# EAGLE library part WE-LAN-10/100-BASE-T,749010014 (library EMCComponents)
LAN-Transformer WE-LAN 10/100 Base T - Compliant with IEEE 802.3 standards - SMD -- Ethernet -- Power over Ethernet -- 1 Gigabit Ethernet -- Compliant with most IC's for ethernet applications like Intel, AMD, Globespan and Realtek -- Hub, Router, Switch

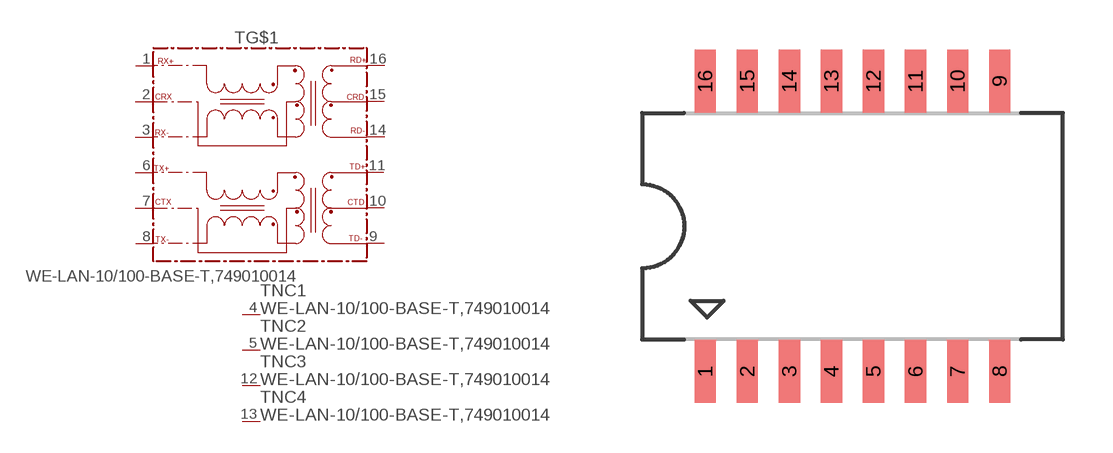
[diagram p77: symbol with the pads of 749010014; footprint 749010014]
Designator prefix T; gates G$1=749010014 NC1=NC NC2=NC NC3=NC NC4=NC

## WE-LAN-10/100-BASE-T,749010014 (COMPANY-URL: http://www.we-online.de; CREATED-BY: Christin Zierenner; CREATED-DATE: June 2012; DATASHEET-URL: http://katalog.we-online.de/kataloge/eisos/media/pdf/749010014.pdf; MANUFACTURER: Würth Elektronik eiSos GmbH)  [749010014]
1  G$1:RX+
2  G$1:CRX
3  G$1:RX-
4  NC1:NC  nc
5  NC2:NC  nc
6  G$1:TX+
7  G$1:CTX
8  G$1:TX-
9  G$1:TD-
10  G$1:CTD
11  G$1:TD+
12  NC3:NC  nc
13  NC4:NC  nc
14  G$1:RD-
15  G$1:CRD
16  G$1:RD+

## Footprint 749010014 (pad centres in mm)
MAX Height =5.08mm
smd 0.64 x 1.91: 1 -4.445,-4.385; 2 -3.175,-4.385; 3 -1.905,-4.385; 4 -0.635,-4.385; 5 0.635,-4.385; 6 1.905,-4.385; 7 3.175,-4.385; 8 4.445,-4.385; 9 4.445,4.385; 10 3.175,4.385; 11 1.905,4.385; 12 0.635,4.385; 13 -0.635,4.385; 14 -1.905,4.385; 15 -3.175,4.385; 16 -4.445,4.385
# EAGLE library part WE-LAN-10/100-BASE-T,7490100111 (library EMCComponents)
LAN-Transformer WE-LAN 10/100 Base T - Compliant with IEEE 802.3 standards - SMD -- Ethernet -- Power over Ethernet -- 1 Gigabit Ethernet -- Compliant with most IC's for ethernet applications like Intel, AMD, Globespan and Realtek -- Hub, Router, Switch

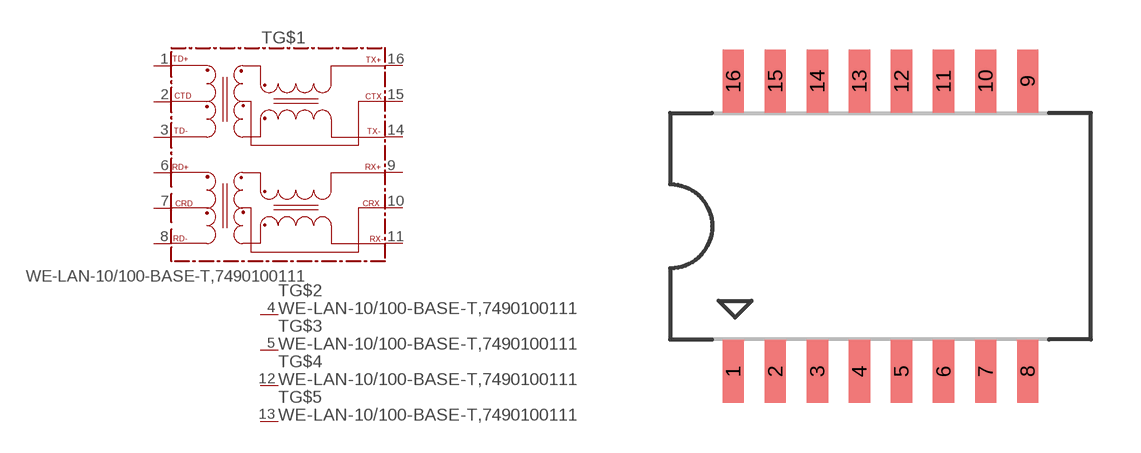
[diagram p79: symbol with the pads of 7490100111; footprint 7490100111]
Designator prefix T; gates G$1=7490100111 G$2=NC G$3=NC G$4=NC G$5=NC

## WE-LAN-10/100-BASE-T,7490100111 (COMPANY-URL: http://www.we-online.de; CREATED-BY: Christin Zierenner; CREATED-DATE: June 2012; DATASHEET-URL: http://katalog.we-online.de/kataloge/eisos/media/pdf/7490100111.pdf; MANUFACTURER: Würth Elektronik eiSos GmbH)  [7490100111]
1  G$1:TD+
2  G$1:CTD
3  G$1:TD-
4  G$2:NC  nc
5  G$3:NC  nc
6  G$1:RD+
7  G$1:CRD
8  G$1:RD-
9  G$1:RX+
10  G$1:CRX
11  G$1:RX-
12  G$4:NC  nc
13  G$5:NC  nc
14  G$1:TX-
15  G$1:CTX
16  G$1:TX+

## Footprint 7490100111 (pad centres in mm)
MAX Height=5.08mm
smd 0.64 x 1.91: 1 -4.445,-4.385; 2 -3.175,-4.385; 3 -1.905,-4.385; 4 -0.635,-4.385; 5 0.635,-4.385; 6 1.905,-4.385; 7 3.175,-4.385; 8 4.445,-4.385; 9 4.445,4.385; 10 3.175,4.385; 11 1.905,4.385; 12 0.635,4.385; 13 -0.635,4.385; 14 -1.905,4.385; 15 -3.175,4.385; 16 -4.445,4.385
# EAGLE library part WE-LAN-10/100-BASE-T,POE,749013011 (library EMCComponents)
LAN-Transformer WE-LAN 10/100 Base Tx - Compliant with IEEE 802.3 standards - SMD -- Ethernet -- Power over Ethernet -- 1 Gigabit Ethernet -- Compliant with most IC's for ethernet applications like Intel, AMD, Globespan and Realtek -- Hub, Router, Switch

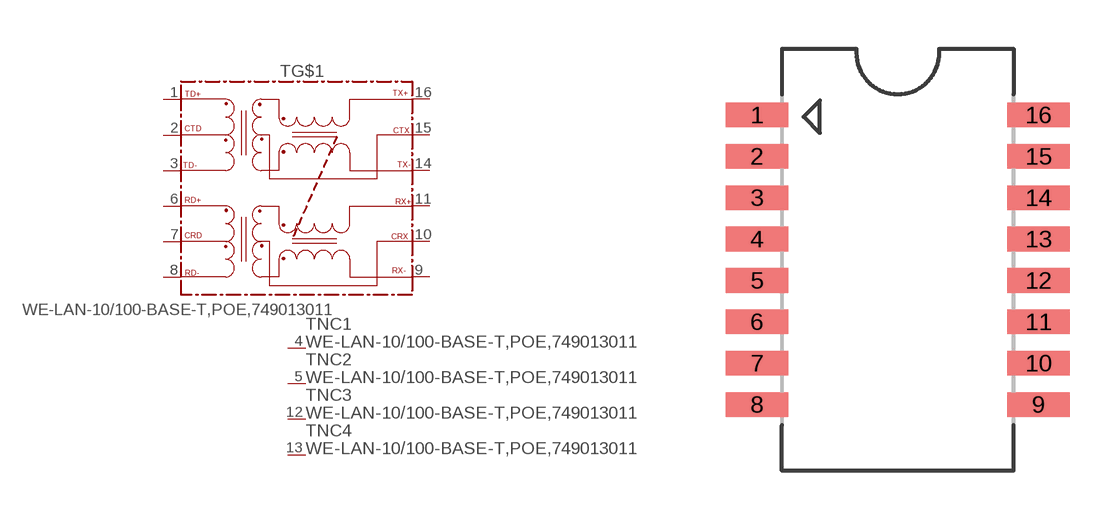
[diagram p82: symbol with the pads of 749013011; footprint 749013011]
Designator prefix T; gates G$1=749013011 NC1=NC NC2=NC NC3=NC NC4=NC

## WE-LAN-10/100-BASE-T,POE,749013011 (COMPANY-URL: http://www.we-online.de; CREATED-BY: Christin Zierenner; CREATED-DATE: June 2012; DATASHEET-URL: http://katalog.we-online.de/kataloge/eisos/media/pdf/749013011.pdf; MANUFACTURER: Würth Elektronik eiSos GmbH)  [749013011]
1  G$1:TD+
2  G$1:CTD
3  G$1:TD-
4  NC1:NC  nc
5  NC2:NC  nc
6  G$1:RD+
7  G$1:CRD
8  G$1:RD-
9  G$1:RX-
10  G$1:CRX
11  G$1:RX+
12  NC3:NC  nc
13  NC4:NC  nc
14  G$1:TX-
15  G$1:CTX
16  G$1:TX+

## Footprint 749013011 (pad centres in mm)
MAX Height = 5.33mm
smd 1.91 x 0.76: 1 -4.317,4.445; 2 -4.317,3.175; 3 -4.317,1.905; 4 -4.317,0.635; 5 -4.317,-0.635; 6 -4.317,-1.905; 7 -4.317,-3.175; 8 -4.317,-4.445; 9 4.317,-4.445; 10 4.317,-3.175; 11 4.317,-1.905; 12 4.317,-0.635; 13 4.317,0.635; 14 4.317,1.905; 15 4.317,3.175; 16 4.317,4.445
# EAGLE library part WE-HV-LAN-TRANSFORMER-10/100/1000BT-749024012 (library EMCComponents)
WE-LAN HV LAN-Transformer Characteristics: •Compliant with IEEE802.3 and 802.3af standards •Operating temperature: 0 °C to +70 °C •SMD •4 kV Hipot test Applications: •Ethernet •Compliant with most IC's for Ethernet applications like Intel, AMD, Conexant, Realtek, etc. •Hub, Router, Switches, medical applications

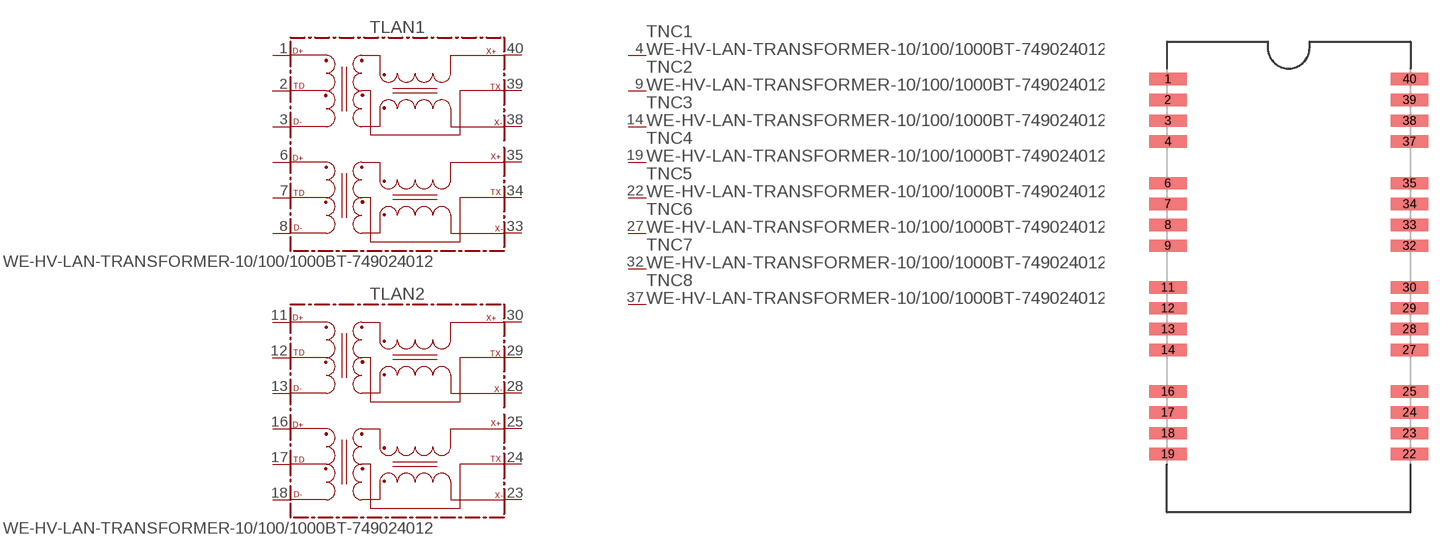
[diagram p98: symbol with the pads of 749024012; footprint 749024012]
Designator prefix T; gates LAN1=749024012 LAN2=749024012 NC1=NC NC2=NC NC3=NC NC4=NC NC5=NC NC6=NC NC7=NC NC8=NC

## WE-HV-LAN-TRANSFORMER-10/100/1000BT-749024012 (COMPANY-URL: http://www.we-online.de; CREATED-BY: Christin Zierenner; CREATED-DATE: July 2012; DATASHEET-URL: http://katalog.we-online.de/kataloge/eisos/media/pdf/749024012.pdf; MANUFACTURER: Würth Elektronik eiSos GmbH)  [749024012]
1  LAN1:D+
2  LAN1:TD
3  LAN1:D-
4  NC1:NC  nc
6  LAN1:D1+
7  LAN1:TD1
8  LAN1:D1-
9  NC2:NC  nc
11  LAN2:D+
12  LAN2:TD
13  LAN2:D-
14  NC3:NC  nc
16  LAN2:D1+
17  LAN2:TD1
18  LAN2:D1-
19  NC4:NC  nc
22  NC5:NC  nc
23  LAN2:X1-
24  LAN2:TX1
25  LAN2:X1+
27  NC6:NC  nc
28  LAN2:X-
29  LAN2:TX
30  LAN2:X+
32  NC7:NC  nc
33  LAN1:X1-
34  LAN1:TX1
35  LAN1:X1+
37  NC8:NC  nc
38  LAN1:X-
39  LAN1:TX
40  LAN1:X+

## Footprint 749024012 (pad centres in mm)
MAX Height=12.70 mm
smd 2.29 x 0.76: 1 -7.365,12.065; 2 -7.365,10.795; 3 -7.365,9.525; 4 -7.365,8.255; 6 -7.365,5.715; 7 -7.365,4.445; 8 -7.365,3.175; 9 -7.365,1.905; 11 -7.365,-0.635; 12 -7.365,-1.905; 13 -7.365,-3.175; 14 -7.365,-4.445; 16 -7.365,-6.985; 17 -7.365,-8.255; 18 -7.365,-9.525; 19 -7.365,-10.795; 22 7.365,-10.795; 23 7.365,-9.525; 24 7.365,-8.255; 25 7.365,-6.985; 27 7.365,-4.445; 28 7.365,-3.175; 29 7.365,-1.905; 30 7.365,-0.635; 32 7.365,1.905; 33 7.365,3.175; 34 7.365,4.445; 35 7.365,5.715; 37 7.365,8.255; 38 7.365,9.525; 39 7.365,10.795; 40 7.365,12.065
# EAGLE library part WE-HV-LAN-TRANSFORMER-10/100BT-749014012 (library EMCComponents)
WE-LAN HV LAN-Transformer Characteristics: •Compliant with IEEE802.3 and 802.3af standards •Operating temperature: 0 °C to +70 °C •SMD •6 kV Hipot test Applications: •Ethernet •Compliant with most IC's for Ethernet applications like Intel, AMD, Conexant, Realtek, etc. •Hub, Router, Switches, medical applications

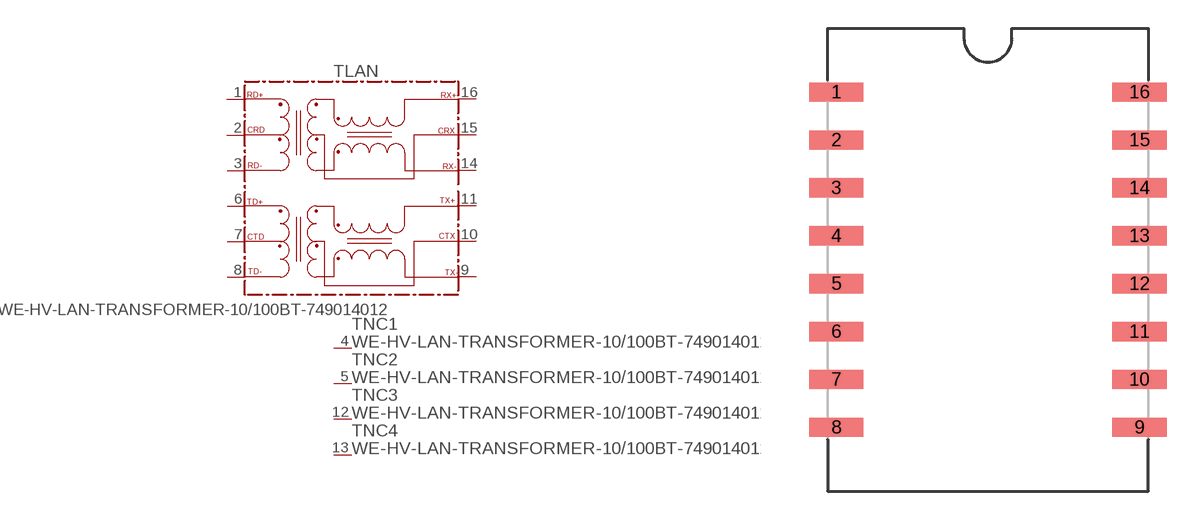
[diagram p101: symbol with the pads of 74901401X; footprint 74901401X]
Designator prefix T; gates LAN=749014012 NC1=NC NC2=NC NC3=NC NC4=NC

## WE-HV-LAN-TRANSFORMER-10/100BT-749014012 (COMPANY-URL: http://www.we-online.de; CREATED-BY: Christin Zierenner; CREATED-DATE: July 2012; DATASHEET-URL: http://katalog.we-online.de/kataloge/eisos/media/pdf/749014012.pdf; MANUFACTURER: Würth Elektronik eiSos GmbH)  [74901401X]
1  LAN:RD+
2  LAN:CRD
3  LAN:RD-
4  NC1:NC  nc
5  NC2:NC  nc
6  LAN:TD+
7  LAN:CTD
8  LAN:TD-
9  LAN:TX-
10  LAN:CTX
11  LAN:TX+
12  NC3:NC  nc
13  NC4:NC  nc
14  LAN:RX-
15  LAN:CRX
16  LAN:RX+

## Footprint 74901401X (pad centres in mm)
MAX Height=10.85 mm
smd 2.87 x 1.02: 1 -8.03,8.89; 2 -8.03,6.35; 3 -8.03,3.81; 4 -8.03,1.27; 5 -8.03,-1.27; 6 -8.03,-3.81; 7 -8.03,-6.35; 8 -8.03,-8.89; 9 8.03,-8.89; 10 8.03,-6.35; 11 8.03,-3.81; 12 8.03,-1.27; 13 8.03,1.27; 14 8.03,3.81; 15 8.03,6.35; 16 8.03,8.89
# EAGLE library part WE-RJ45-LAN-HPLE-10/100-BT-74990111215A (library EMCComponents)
Order Code 74990111215A Design THT xBase-T 10/100 Base-T Ports 1x1 Application Standard HPLE Tab Position Down LED (Left-Right) YELLOW-GREEN EMI Fingers YES

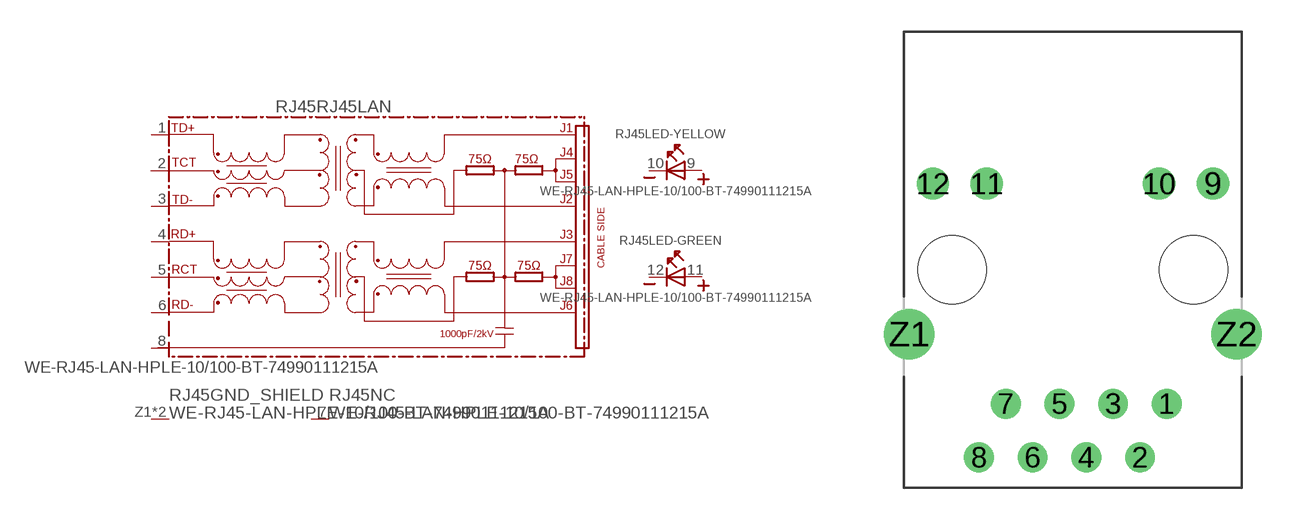
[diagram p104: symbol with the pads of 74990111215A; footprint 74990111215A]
Designator prefix RJ45; gates RJ45LAN=74990111215A LED-YELLOW=LED-2PIN LED-GREEN=LED-2PIN GND_SHIELD=GND_PIN NC=NC

## WE-RJ45-LAN-HPLE-10/100-BT-74990111215A (COMPANY-URL: http://www.we-online.de; CREATED-BY: Christin Zierenner; CREATED-DATE: AUG 2012; DATASHEET-URL: http://katalog.we-online.de/kataloge/eisos/media/pdf/74990111215A.pdf; MANUFACTURER: Würth Elektronik eiSos GmbH)  [74990111215A]
1  RJ45LAN:TD+
2  RJ45LAN:TCT
3  RJ45LAN:TD-
4  RJ45LAN:RD+
5  RJ45LAN:RCT
6  RJ45LAN:RD-
7  NC:NC  nc
8  RJ45LAN:SH  pwr
9  LED-YELLOW:A
10  LED-YELLOW:K
11  LED-GREEN:A
12  LED-GREEN:K
Z1  GND_SHIELD:P$1  pwr
Z2  GND_SHIELD:P$1  pwr

## Footprint 74990111215A (pad centres in mm)
MAX HEIGHT=13.74mm PORTS----1X1 LED --YES
drill 0.9: 1 4.445,-6.35; 2 3.175,-8.89; 3 1.905,-6.35; 4 0.635,-8.89; 5 -0.635,-6.35; 6 -1.905,-8.89; 7 -3.175,-6.35; 8 -4.445,-8.89
drill 1.02: 9 6.625,4.08; 10 4.085,4.08; 11 -4.085,4.08; 12 -6.625,4.08
drill 1.6: Z1 -7.745,-3.05; Z2 7.745,-3.05
hole 3.25 at 5.715,0
hole 3.25 at -5.715,0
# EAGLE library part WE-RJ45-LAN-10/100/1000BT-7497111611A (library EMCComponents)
Order Code 7497111611A Design THT xBase-T 10/100/1000 Base-T Ports 1x1 + 2xUSB Application Standard USB2.0 Tab Position UP LED (Left-Right) GREEN/ORANGE-YELLOW EMI Fingers YES

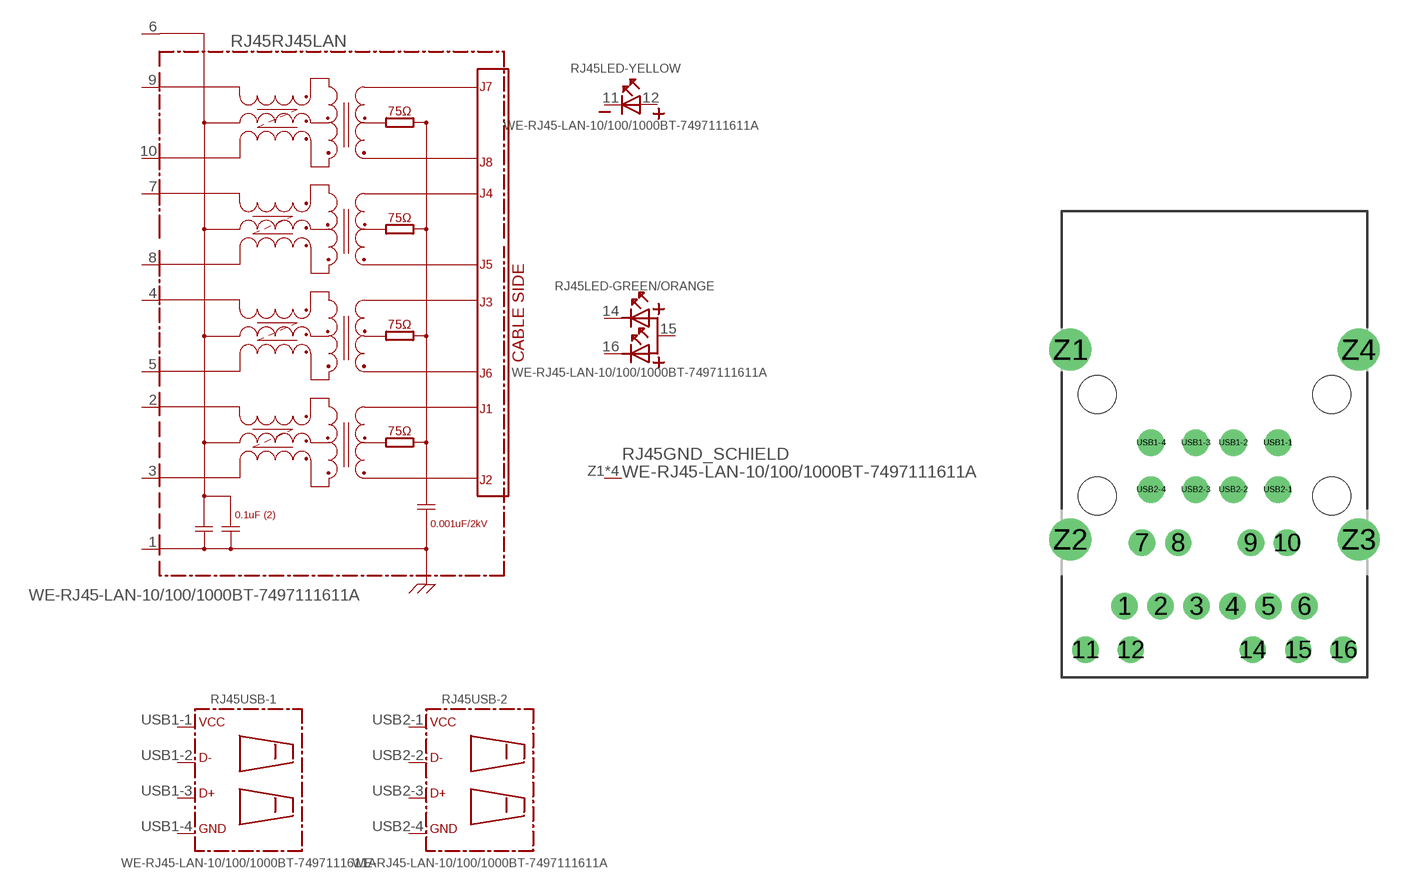
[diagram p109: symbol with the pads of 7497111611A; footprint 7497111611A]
Designator prefix RJ45; gates RJ45LAN=7497111611A LED-YELLOW=LED2PIN LED-GREEN/ORANGE=LED-DUAL1 USB-1=USB2.0 USB-2=USB2.0 GND_SCHIELD=GND_PIN

## WE-RJ45-LAN-10/100/1000BT-7497111611A (COMPANY-URL: http://www.we-online.de; CREATED-BY: Christin Zierenner; CREATED-DATE: AUG 2012; DATASHEET-URL: http://katalog.we-online.de/kataloge/eisos/media/pdf/7497111611A.pdf; MANUFACTURER: Würth Elektronik eiSos GmbH)  [7497111611A]
1  RJ45LAN:1  pwr
2  RJ45LAN:2
3  RJ45LAN:3
4  RJ45LAN:4
5  RJ45LAN:5
6  RJ45LAN:6
7  RJ45LAN:7
8  RJ45LAN:8
9  RJ45LAN:9
10  RJ45LAN:10
11  LED-YELLOW:K
12  LED-YELLOW:A
14  LED-GREEN/ORANGE:K1
15  LED-GREEN/ORANGE:A1
16  LED-GREEN/ORANGE:K2
USB1-1  USB-1:VCC  pwr
USB1-2  USB-1:D-
USB1-3  USB-1:D+
USB1-4  USB-1:GND  pwr
USB2-1  USB-2:VCC  pwr
USB2-2  USB-2:D-
USB2-3  USB-2:D+
USB2-4  USB-2:GND  pwr
Z1  GND_SCHIELD:P$1  pwr
Z2  GND_SCHIELD:P$1  pwr
Z3  GND_SCHIELD:P$1  pwr
Z4  GND_SCHIELD:P$1  pwr

## Footprint 7497111611A (pad centres in mm)
MAX HEIGHT=13.50mm PORTS----1X1 + 2XUSB (USB2.0) LED -YES
drill 0.97: 1 -5.025,-14.35; 2 -3.015,-14.35; 3 -1.005,-14.35; 4 1.005,-14.35; 5 3.015,-14.35; 6 5.025,-14.35; 7 -4.065,-10.8; 8 -2.03,-10.8; 9 2.03,-10.8; 10 4.065,-10.8; 11 -7.225,-16.78; 12 -4.685,-16.78; 14 2.14,-16.78; 15 4.685,-16.78; 16 7.225,-16.78; USB1-1 3.55,-5.21; USB1-2 1.05,-5.21; USB1-3 -1.05,-5.21; USB1-4 -3.55,-5.21; USB2-1 3.55,-7.83; USB2-2 1.05,-7.83; USB2-3 -1.05,-7.83; USB2-4 -3.55,-7.83
drill 1.57: Z1 -8.065,0; Z2 -8.065,-10.62; Z3 8.065,-10.62; Z4 8.065,0
hole 2.13 at 6.565,-2.51
hole 2.13 at -6.565,-2.51
hole 2.13 at -6.565,-8.2
hole 2.13 at 6.565,-8.2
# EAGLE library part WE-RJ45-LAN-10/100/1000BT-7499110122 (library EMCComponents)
Order Code 7499110122 Design THT xBase-T 10/100/1000 Base-T Ports 1x1 Application Standard Tab Position Down LED (Left-Right) YELLOW-GREEN EMI Fingers No

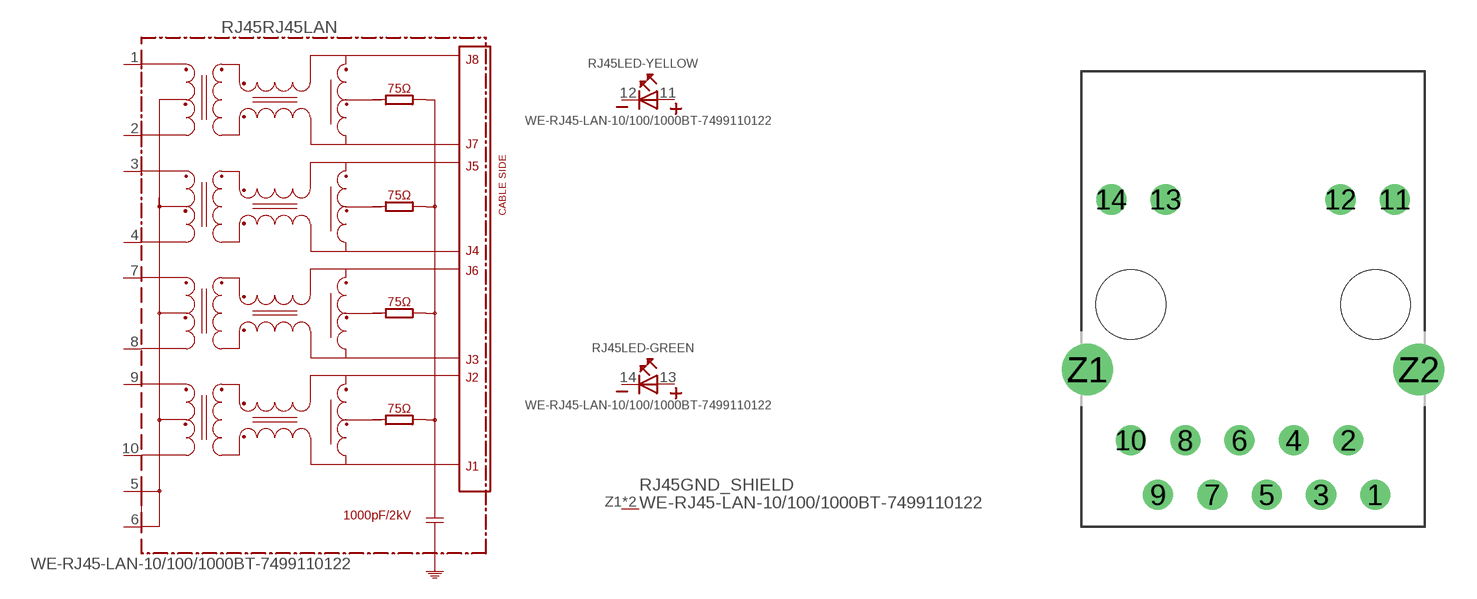
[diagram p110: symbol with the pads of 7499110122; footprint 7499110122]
Designator prefix RJ45; gates RJ45LAN=7499110122 LED-YELLOW=LED2PIN LED-GREEN=LED2PIN GND_SHIELD=GNDPIN

## WE-RJ45-LAN-10/100/1000BT-7499110122 (COMPANY-URL: http://www.we-online.de; CREATED-BY: Christin Zierenner; CREATED-DATE: AUG 2012; DATASHEET-URL: http://katalog.we-online.de/kataloge/eisos/media/pdf/7499110122.pdf; MANUFACTURER: Würth Elektronik eiSos GmbH)  [7499110122]
1  RJ45LAN:1
2  RJ45LAN:2
3  RJ45LAN:3
4  RJ45LAN:4
5  RJ45LAN:5
6  RJ45LAN:6
7  RJ45LAN:7
8  RJ45LAN:8
9  RJ45LAN:9
10  RJ45LAN:10
11  LED-YELLOW:A
12  LED-YELLOW:K
13  LED-GREEN:A
14  LED-GREEN:K
Z1  GND_SHIELD:P$1  pwr
Z2  GND_SHIELD:P$1  pwr

## Footprint 7499110122 (pad centres in mm)
MAX HEIGHT=13.50mm PORTS----1X1 LED -YES
drill 0.9: 1 5.715,-8.89; 2 4.445,-6.35; 3 3.175,-8.89; 4 1.905,-6.35; 5 0.635,-8.89; 6 -0.635,-6.35; 7 -1.905,-8.89; 8 -3.175,-6.35; 9 -4.445,-8.89; 10 -5.715,-6.35; 11 6.63,4.9; 12 4.09,4.9; 13 -4.09,4.9; 14 -6.63,4.9
drill 1.6: Z1 -7.745,-3.05; Z2 7.745,-3.05
hole 3.25 at 5.715,0
hole 3.25 at -5.715,0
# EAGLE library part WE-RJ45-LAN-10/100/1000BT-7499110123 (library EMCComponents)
Order Code 7499110123 Design THT xBase-T 10/100/1000 Base-T Ports 1x1 Application Standard Tab Position VERTICAL LED (Left-Right) YELLOW-GREEN EMI Fingers No

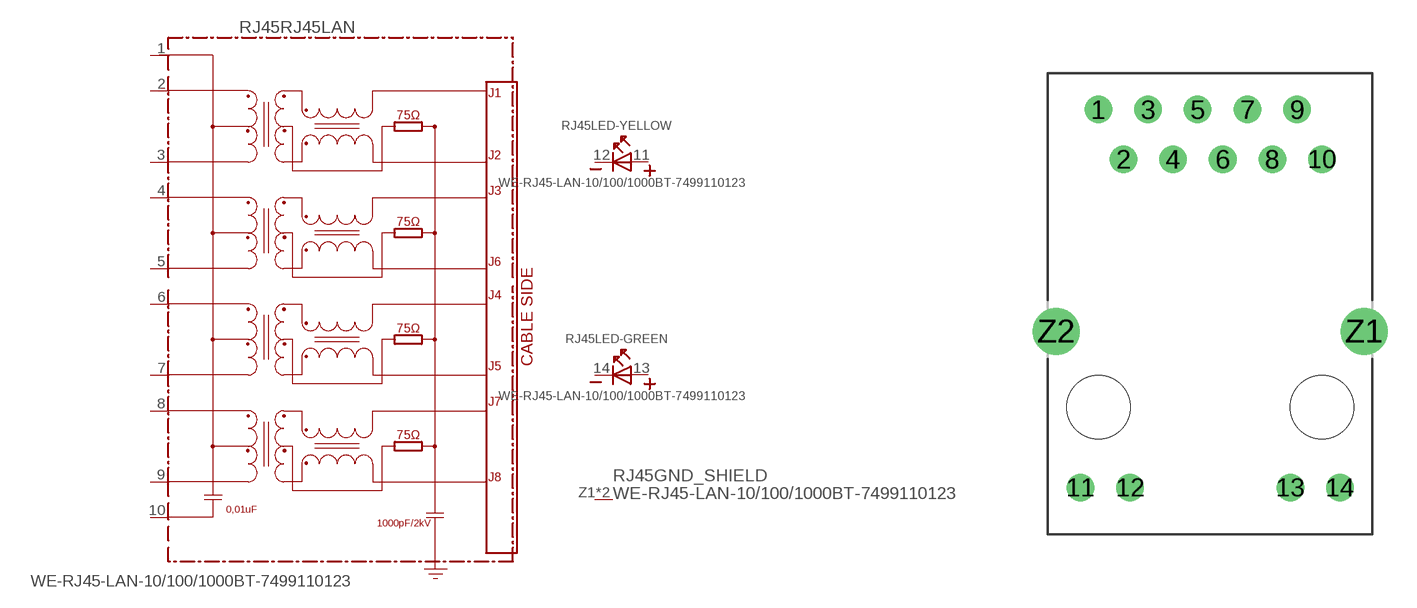
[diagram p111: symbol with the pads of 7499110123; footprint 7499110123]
Designator prefix RJ45; gates RJ45LAN=7499110123 LED-YELLOW=LED2PIN LED-GREEN=LED2PIN GND_SHIELD=GNDPIN

## WE-RJ45-LAN-10/100/1000BT-7499110123 (COMPANY-URL: http://www.we-online.de; CREATED-BY: Christin Zierenner; CREATED-DATE: AUG 2012; DATASHEET-URL: http://katalog.we-online.de/kataloge/eisos/media/pdf/7499110123.pdf; MANUFACTURER: Würth Elektronik eiSos GmbH)  [7499110123]
1  RJ45LAN:1
2  RJ45LAN:2
3  RJ45LAN:3
4  RJ45LAN:4
5  RJ45LAN:5
6  RJ45LAN:6
7  RJ45LAN:7
8  RJ45LAN:8
9  RJ45LAN:9
10  RJ45LAN:10
11  LED-YELLOW:A
12  LED-YELLOW:K
13  LED-GREEN:A
14  LED-GREEN:K
Z1  GND_SHIELD:P$1  pwr
Z2  GND_SHIELD:P$1  pwr

## Footprint 7499110123 (pad centres in mm)
MAX HEIGHT=17.10mm PORTS----1X1 LED -YES
drill 0.9: 1 -5.72,15.24; 2 -4.44,12.7; 3 -3.18,15.24; 4 -1.9,12.7; 5 -0.64,15.24; 6 0.64,12.7; 7 1.9,15.24; 8 3.18,12.7; 9 4.44,15.24; 10 5.72,12.7; 11 -6.635,-4.11; 12 -4.095,-4.11; 13 4.095,-4.11; 14 6.635,-4.11
drill 1.6: Z1 7.875,3.89; Z2 -7.875,3.89
hole 3.25 at -5.715,0
hole 3.25 at 5.715,0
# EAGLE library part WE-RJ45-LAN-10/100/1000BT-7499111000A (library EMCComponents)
Order Code 7499111000A Design THT xBase-T 10/100/1000 Base-T Ports 1x1 Application Standard Tab Position UP LED (Left-Right) NONE EMI Fingers Yes

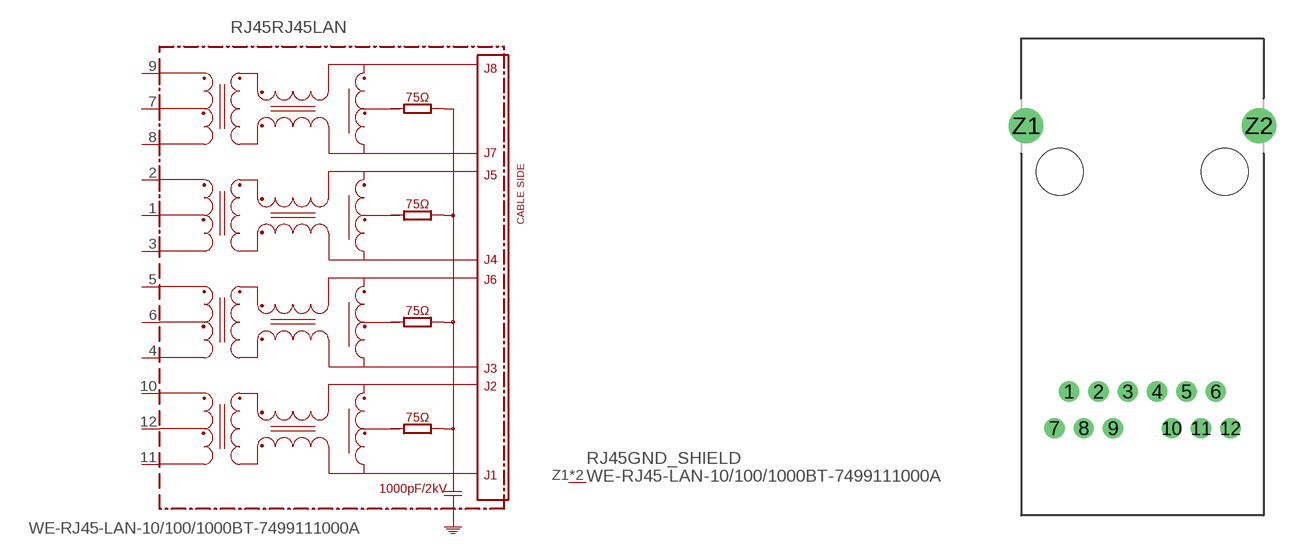
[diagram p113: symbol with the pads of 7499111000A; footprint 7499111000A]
Designator prefix RJ45; gates RJ45LAN=7499111221A/7499111000A GND_SHIELD=GNDPIN

## WE-RJ45-LAN-10/100/1000BT-7499111000A (COMPANY-URL: http://www.we-online.de; CREATED-BY: Christin Zierenner; CREATED-DATE: AUG 2012; DATASHEET-URL: http://katalog.we-online.de/kataloge/eisos/media/pdf/7499111000A.pdf; MANUFACTURER: Würth Elektronik eiSos GmbH)  [7499111000A]
1  RJ45LAN:1
2  RJ45LAN:2
3  RJ45LAN:3
4  RJ45LAN:4
5  RJ45LAN:5
6  RJ45LAN:6
7  RJ45LAN:7
8  RJ45LAN:8
9  RJ45LAN:9
10  RJ45LAN:10
11  RJ45LAN:11
12  RJ45LAN:12
Z1  GND_SHIELD:P$1  pwr
Z2  GND_SHIELD:P$1  pwr

## Footprint 7499111000A (pad centres in mm)
MAX HEIGHT=15.79mm PORTS----1X1 LED --NO
drill 0.9: 1 -5.075,-15.24; 2 -3.045,-15.24; 3 -1.015,-15.24; 4 1.015,-15.24; 5 3.045,-15.24; 6 5.075,-15.24; 7 -6.095,-17.78; 8 -4.065,-17.78; 9 -2.035,-17.78; 10 2.035,-17.78; 11 4.065,-17.78; 12 6.095,-17.78
drill 1.6: Z1 -8.065,3.18; Z2 8.065,3.18
hole 3.25 at 5.715,0
hole 3.25 at -5.715,0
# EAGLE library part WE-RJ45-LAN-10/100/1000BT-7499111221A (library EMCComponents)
Order Code 7499111221A Design THT xBase-T 10/100/1000 Base-T Ports 1x1 Application Standard Tab Position UP LED (Left-Right) GREEN-GREEN EMI Fingers Yes

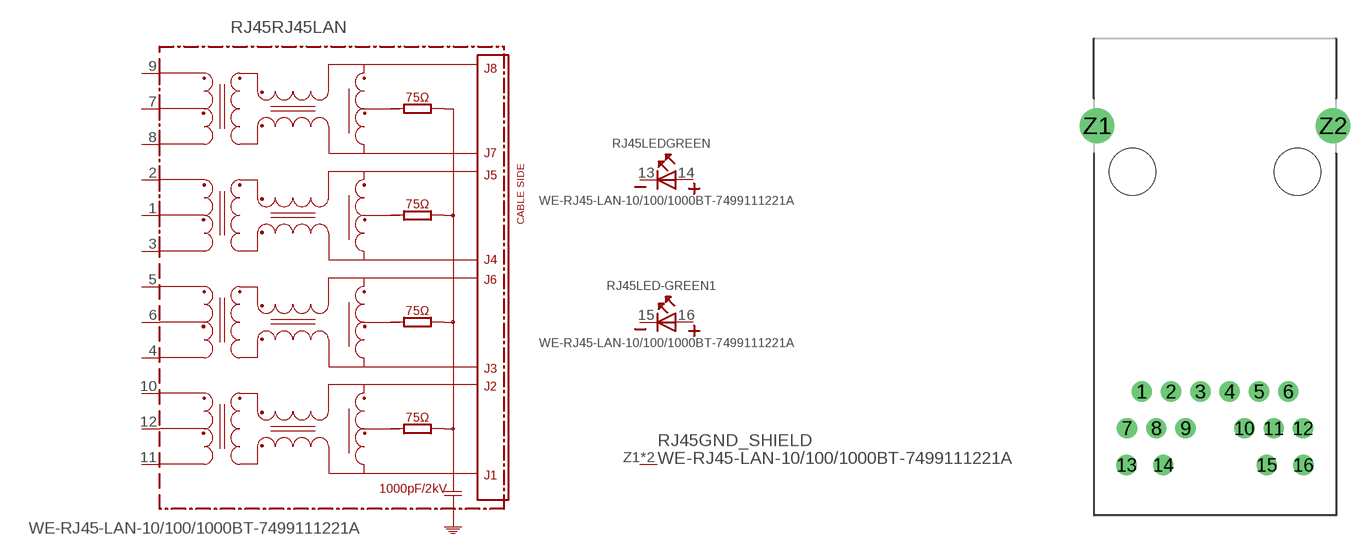
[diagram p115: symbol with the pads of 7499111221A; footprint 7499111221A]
Designator prefix RJ45; gates RJ45LAN=7499111221A/7499111000A LEDGREEN=LED2PIN LED-GREEN1=LED2PIN GND_SHIELD=GNDPIN

## WE-RJ45-LAN-10/100/1000BT-7499111221A (COMPANY-URL: http://www.we-online.de; CREATED-BY: Christin Zierenner; CREATED-DATE: AUG 2012; DATASHEET-URL: http://katalog.we-online.de/kataloge/eisos/media/pdf/7499111221A.pdf; MANUFACTURER: Würth Elektronik eiSos GmbH)  [7499111221A]
1  RJ45LAN:1
2  RJ45LAN:2
3  RJ45LAN:3
4  RJ45LAN:4
5  RJ45LAN:5
6  RJ45LAN:6
7  RJ45LAN:7
8  RJ45LAN:8
9  RJ45LAN:9
10  RJ45LAN:10
11  RJ45LAN:11
12  RJ45LAN:12
13  LEDGREEN:K
14  LEDGREEN:A
15  LED-GREEN1:K
16  LED-GREEN1:A
Z1  GND_SHIELD:P$1  pwr
Z2  GND_SHIELD:P$1  pwr

## Footprint 7499111221A (pad centres in mm)
MAX HEIGHT=15.79mm PORTS----1X1 LED --YES
drill 0.9: 1 -5.075,-15.24; 2 -3.045,-15.24; 3 -1.015,-15.24; 4 1.015,-15.24; 5 3.045,-15.24; 6 5.075,-15.24; 7 -6.095,-17.78; 8 -4.065,-17.78; 9 -2.035,-17.78; 10 2.035,-17.78; 11 4.065,-17.78; 12 6.095,-17.78; 13 -6.12,-20.32; 14 -3.58,-20.32; 15 3.58,-20.32; 16 6.12,-20.32
drill 1.6: Z1 -8.175,3.18; Z2 8.175,3.18
hole 3.25 at 5.715,0
hole 3.25 at -5.715,0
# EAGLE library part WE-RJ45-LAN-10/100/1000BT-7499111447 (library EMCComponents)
Order Code 7499111447 Design THT xBase-T 10/100/1000 Base-T Ports 1x1 Application Standard Tab Position Up LED (Left-Right) GREEN/YELLOW-GREEN/YELLOW EMI Fingers yes

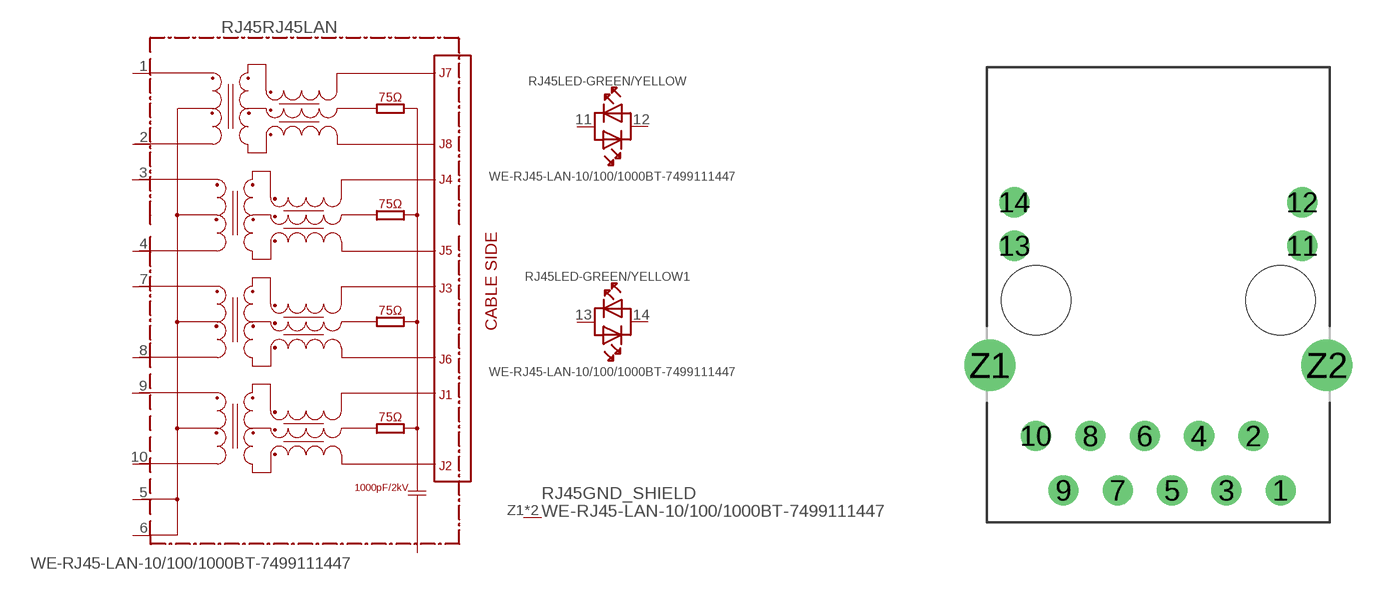
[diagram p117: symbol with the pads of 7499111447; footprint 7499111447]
Designator prefix RJ45; gates RJ45LAN=7499111447 LED-GREEN/YELLOW=LED-DUAL-1 LED-GREEN/YELLOW1=LED-DUAL-1 GND_SHIELD=GNDPIN

## WE-RJ45-LAN-10/100/1000BT-7499111447 (COMPANY-URL: http://www.we-online.de; CREATED-BY: Christin Zierenner; CREATED-DATE: AUG 2012; DATASHEET-URL: http://katalog.we-online.de/kataloge/eisos/media/pdf/7499111447.pdf; MANUFACTURER: Würth Elektronik eiSos GmbH)  [7499111447]
1  RJ45LAN:1
2  RJ45LAN:2
3  RJ45LAN:3
4  RJ45LAN:4
5  RJ45LAN:5
6  RJ45LAN:6
7  RJ45LAN:7
8  RJ45LAN:8
9  RJ45LAN:9
10  RJ45LAN:10
11  LED-GREEN/YELLOW:AK1
12  LED-GREEN/YELLOW:AK2
13  LED-GREEN/YELLOW1:AK1
14  LED-GREEN/YELLOW1:AK2
Z1  GND_SHIELD:P$1  pwr
Z2  GND_SHIELD:P$1  pwr

## Footprint 7499111447 (pad centres in mm)
MAX HEIGHT=13.55mm PORTS----1X1 LED -YES
drill 0.9: 1 5.72,-8.89; 2 4.44,-6.35; 3 3.18,-8.89; 4 1.9,-6.35; 5 0.64,-8.89; 6 -0.64,-6.35; 7 -1.9,-8.89; 8 -3.18,-6.35; 9 -4.44,-8.89; 10 -5.72,-6.35; 11 6.725,2.54; 12 6.725,4.57; 13 -6.725,2.54; 14 -6.725,4.57
drill 1.6: Z1 -7.875,-3.05; Z2 7.875,-3.05
hole 3.25 at 5.715,0
hole 3.25 at -5.715,0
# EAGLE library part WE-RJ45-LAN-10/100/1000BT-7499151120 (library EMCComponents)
Order Code 7499151120 Design THT xBase-T 10/100/1000 Base-T Ports 1x2 Stacked Application Standard Tab Position UP & DOWN LED (Left-Right) YELLOW-GREEN EMI Fingers Yes

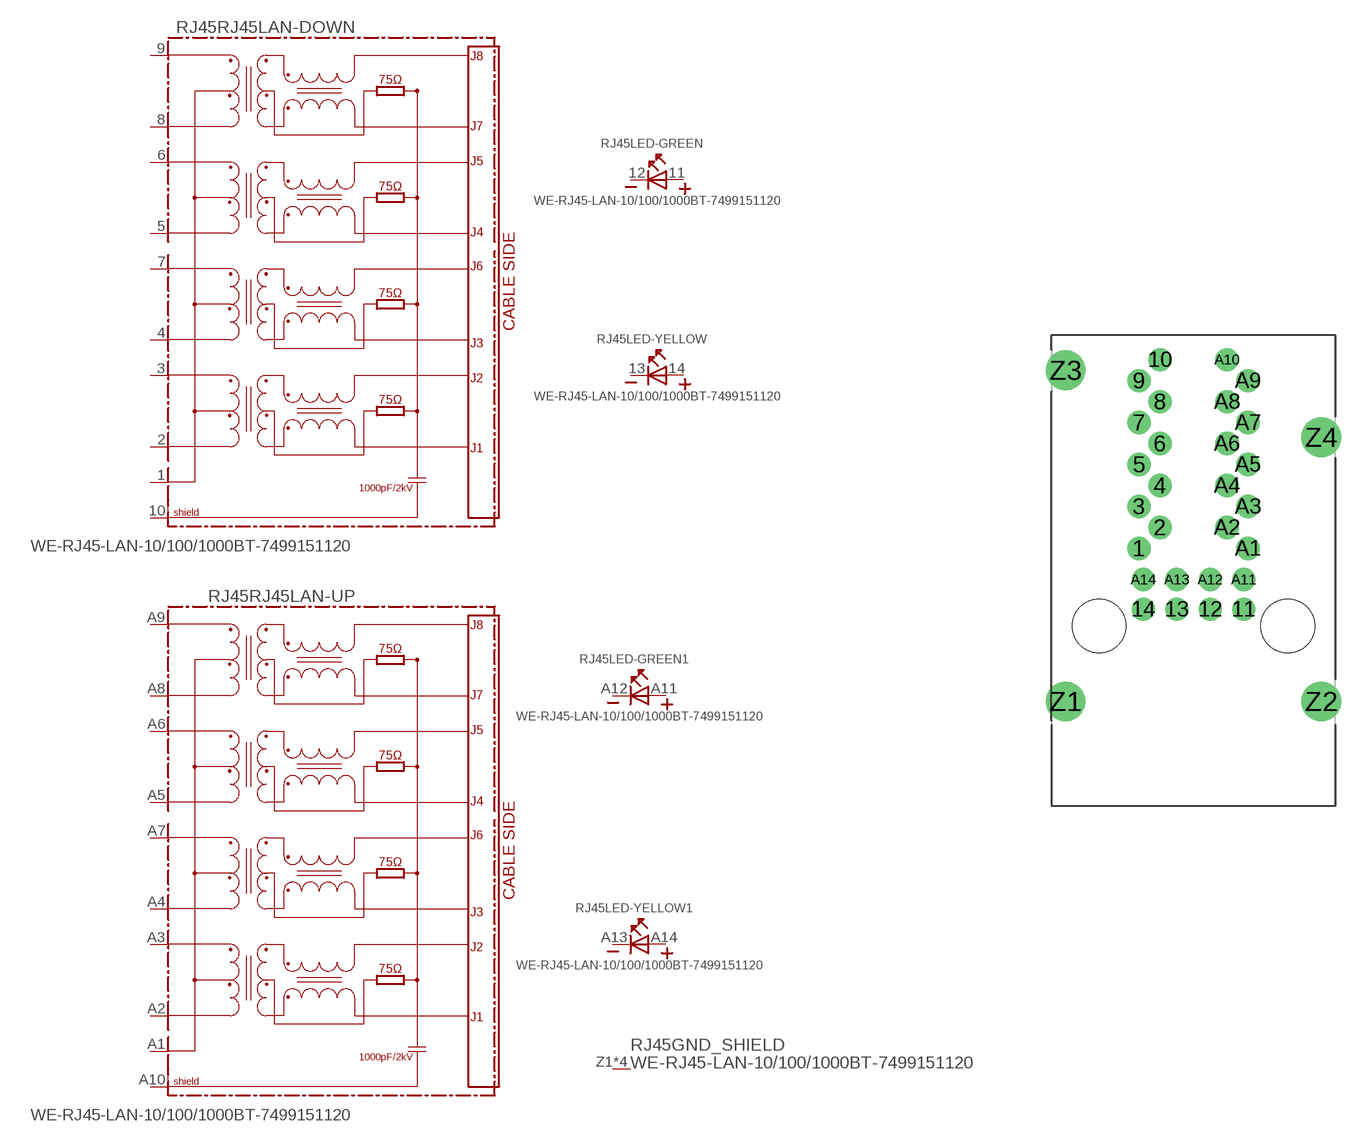
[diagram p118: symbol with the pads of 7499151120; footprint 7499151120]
Designator prefix RJ45; gates RJ45LAN-DOWN=7499151120 RJ45LAN-UP=7499151120 LED-GREEN=LED2PIN LED-YELLOW=LED2PIN LED-GREEN1=LED2PIN LED-YELLOW1=LED2PIN GND_SHIELD=GND_PIN

## WE-RJ45-LAN-10/100/1000BT-7499151120 (COMPANY-URL: http://www.we-online.de; CREATED-BY: Christin Zierenner; CREATED-DATE: AUG 2012; DATASHEET-URL: http://katalog.we-online.de/kataloge/eisos/media/pdf/7499151120.pdf; MANUFACTURER: Würth Elektronik eiSos GmbH)  [7499151120]
1  RJ45LAN-DOWN:1
2  RJ45LAN-DOWN:2
3  RJ45LAN-DOWN:3
4  RJ45LAN-DOWN:4
5  RJ45LAN-DOWN:5
6  RJ45LAN-DOWN:6
7  RJ45LAN-DOWN:7
8  RJ45LAN-DOWN:8
9  RJ45LAN-DOWN:9
10  RJ45LAN-DOWN:SHIELD  pwr
11  LED-GREEN:A
12  LED-GREEN:K
13  LED-YELLOW:K
14  LED-YELLOW:A
A1  RJ45LAN-UP:1
A2  RJ45LAN-UP:2
A3  RJ45LAN-UP:3
A4  RJ45LAN-UP:4
A5  RJ45LAN-UP:5
A6  RJ45LAN-UP:6
A7  RJ45LAN-UP:7
A8  RJ45LAN-UP:8
A9  RJ45LAN-UP:9
A10  RJ45LAN-UP:SHIELD  pwr
A11  LED-GREEN1:A
A12  LED-GREEN1:K
A13  LED-YELLOW1:K
A14  LED-YELLOW1:A
Z1  GND_SHIELD:P$1  pwr
Z2  GND_SHIELD:P$1  pwr
Z3  GND_SHIELD:P$1  pwr
Z4  GND_SHIELD:P$1  pwr

## Footprint 7499151120 (pad centres in mm)
MAX HEIGHT=26.0mm PORTS----1X2 LED -YES
drill 0.9: 1 -3.3,4.7; 2 -2.03,5.97; 3 -3.3,7.24; 4 -2.03,8.51; 5 -3.3,9.78; 6 -2.03,11.05; 7 -3.3,12.32; 8 -2.03,13.59; 9 -3.3,14.86; 10 -2.03,16.13; 11 3.045,1.01; 12 1.015,1.01; 13 -1.015,1.01; 14 -3.045,1.01; A1 3.3,4.7; A2 2.03,5.97; A3 3.3,7.24; A4 2.03,8.51; A5 3.3,9.78; A6 2.03,11.05; A7 3.3,12.32; A8 2.03,13.59; A9 3.3,14.86; A10 2.03,16.13; A11 3.045,2.81; A12 1.015,2.81; A13 -1.015,2.81; A14 -3.045,2.81
drill 1.6: Z1 -7.745,-4.57; Z2 7.745,-4.57; Z3 -7.745,15.49; Z4 7.745,11.43
hole 3.25 at 5.715,0
hole 3.25 at -5.715,0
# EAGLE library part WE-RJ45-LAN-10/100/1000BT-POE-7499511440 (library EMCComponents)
Order Code 7499511440 Design THT xBase-T 10/100/1000 Base-T Ports 1x1 Application PoE Tab Position UP LED (Left-Right) GREEN/YELLOW-GREEN/YELLOW EMI Fingers Yes

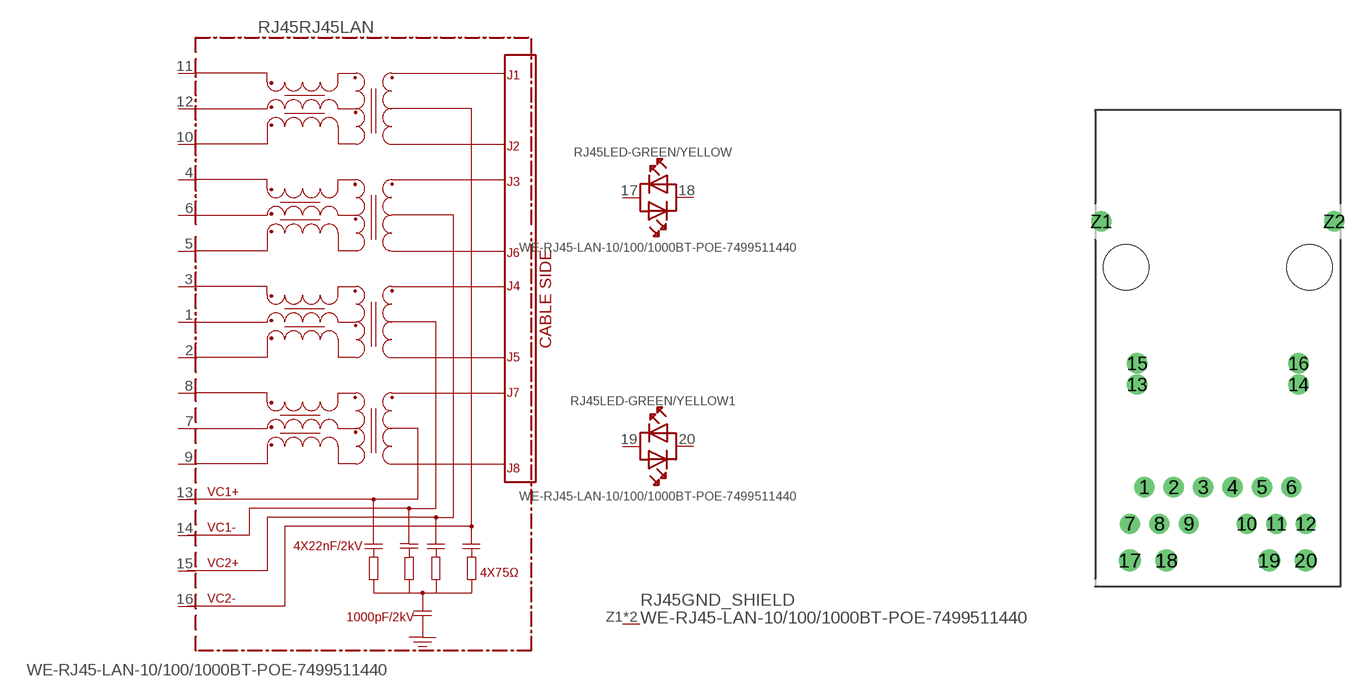
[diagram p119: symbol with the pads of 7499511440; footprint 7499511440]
Designator prefix RJ45; gates RJ45LAN=7499511440 LED-GREEN/YELLOW=LED-DUAL-1 LED-GREEN/YELLOW1=LED-DUAL-1 GND_SHIELD=GNDPIN

## WE-RJ45-LAN-10/100/1000BT-POE-7499511440 (COMPANY-URL: http://www.we-online.de; CREATED-BY: Christin Zierenner; CREATED-DATE: AUG 2012; DATASHEET-URL: http://katalog.we-online.de/kataloge/eisos/media/pdf/7499511440.pdf; MANUFACTURER: Würth Elektronik eiSos GmbH)  [7499511440]
1  RJ45LAN:1
2  RJ45LAN:2
3  RJ45LAN:3
4  RJ45LAN:4
5  RJ45LAN:5
6  RJ45LAN:6
7  RJ45LAN:7
8  RJ45LAN:8
9  RJ45LAN:9
10  RJ45LAN:10
11  RJ45LAN:11
12  RJ45LAN:12
13  RJ45LAN:VC1+1  pwr
14  RJ45LAN:VC1-1  pwr
15  RJ45LAN:VC2+1  pwr
16  RJ45LAN:VC2-1  pwr
17  LED-GREEN/YELLOW:AK1
18  LED-GREEN/YELLOW:AK2
19  LED-GREEN/YELLOW1:AK1
20  LED-GREEN/YELLOW1:AK2
Z1  GND_SHIELD:P$1  pwr
Z2  GND_SHIELD:P$1  pwr

## Footprint 7499511440 (pad centres in mm)
MAX HEIGHT=13.87mm PORTS----1X1 LED -YES
drill 0.9: 1 -5.095,-15.24; 2 -3.055,-15.24; 3 -1.015,-15.24; 4 1.015,-15.24; 5 3.055,-15.24; 6 5.095,-15.24; 7 -6.09,-17.78; 8 -4.05,-17.78; 9 -2.01,-17.78; 10 2.01,-17.78; 11 4.05,-17.78; 12 6.09,-17.78; 13 -5.59,-8.12; 14 5.59,-8.12; 15 -5.59,-6.66; 16 5.59,-6.66; Z1 -8.065,3.18; Z2 8.065,3.18
drill 1.02: 17 -6.095,-20.32; 18 -3.555,-20.32; 19 3.555,-20.32; 20 6.095,-20.32
hole 3.15 at -6.35,0
hole 3.15 at 6.35,0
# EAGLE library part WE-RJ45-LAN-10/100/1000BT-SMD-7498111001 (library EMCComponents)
Order Code 7498111001 Design SMD xBase-T 10/100/1000 Base-T Ports 1x1 Application Standard Tab Position UP LED (Left-Right) NONE EMI Fingers Yes

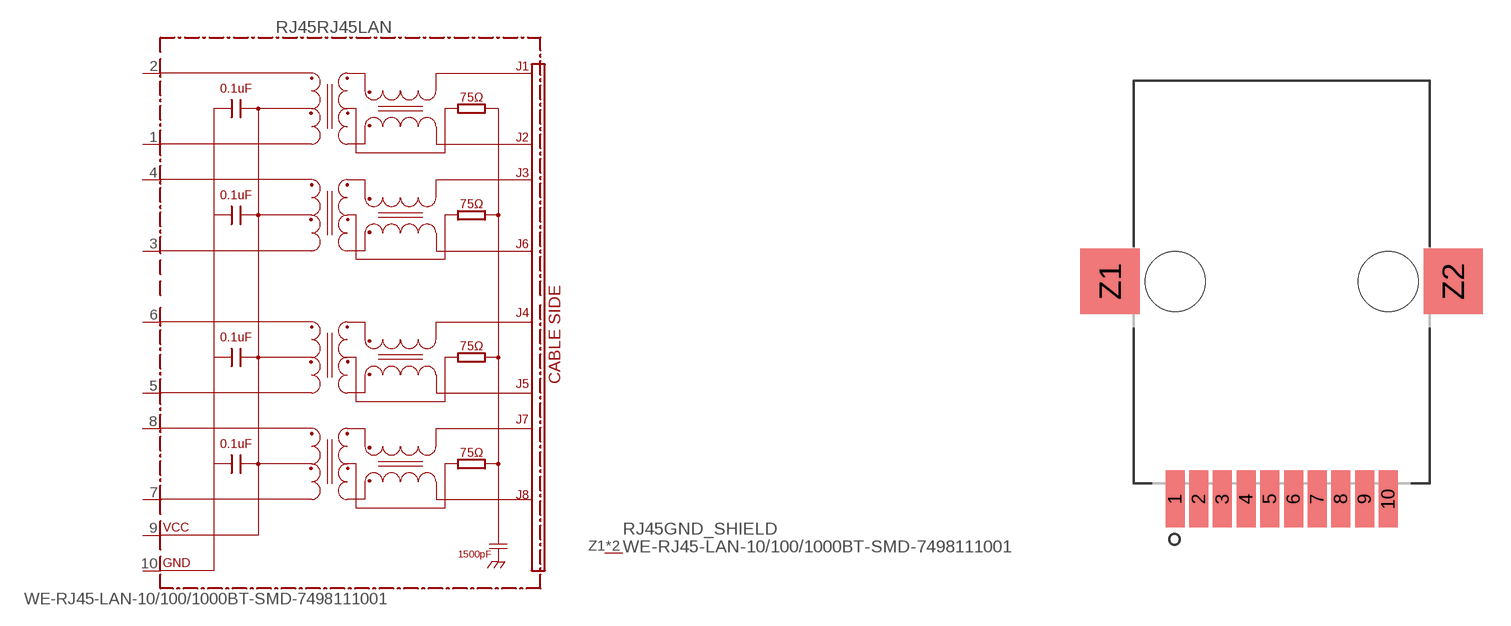
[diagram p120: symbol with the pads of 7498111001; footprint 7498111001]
Designator prefix RJ45; gates RJ45LAN=7498111001 GND_SHIELD=GNDPIN

## WE-RJ45-LAN-10/100/1000BT-SMD-7498111001 (COMPANY-URL: http://www.we-online.de; CREATED-BY: Christin Zierenner; CREATED-DATE: AUG 2012; DATASHEET-URL: http://katalog.we-online.de/kataloge/eisos/media/pdf/7498111001.pdf; MANUFACTURER: Würth Elektronik eiSos GmbH)  [7498111001]
1  RJ45LAN:1
2  RJ45LAN:2
3  RJ45LAN:3
4  RJ45LAN:4
5  RJ45LAN:5
6  RJ45LAN:6
7  RJ45LAN:7
8  RJ45LAN:8
9  RJ45LAN:VCC  pwr
10  RJ45LAN:GND  pwr
Z1  GND_SHIELD:P$1  pwr
Z2  GND_SHIELD:P$1  pwr

## Footprint 7498111001 (pad centres in mm)
MAX HEIGHT=13.55mm PORTS----1X1 LED -NO
smd 1.02 x 3.05: 1 -5.715,-11.68; 2 -4.445,-11.68; 3 -3.175,-11.68; 4 -1.905,-11.68; 5 -0.635,-11.68; 6 0.635,-11.68; 7 1.905,-11.68; 8 3.175,-11.68; 9 4.445,-11.68; 10 5.715,-11.68
smd 3.18 x 3.5: Z1 -9.2,0; Z2 9.2,0
hole 3.22 at 5.715,0
hole 3.22 at -5.715,0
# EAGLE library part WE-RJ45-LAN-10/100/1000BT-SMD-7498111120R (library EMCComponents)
Order Code 7498111120R Design SMD xBase-T 10/100/1000 Base-T Ports 1x1 Application Standard Tab Position UP LED (Left-Right) YELLOW-GREEN EMI Fingers Yes

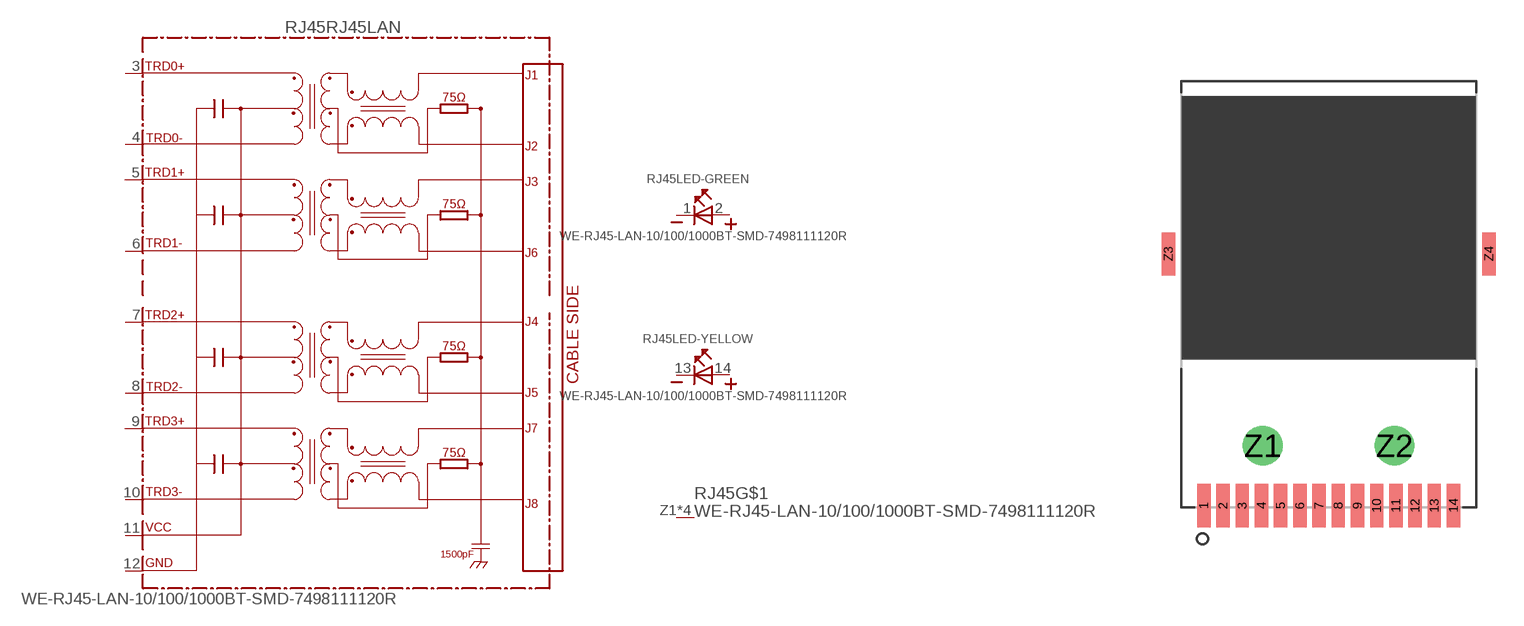
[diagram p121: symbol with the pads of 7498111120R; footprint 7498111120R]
Designator prefix RJ45; gates RJ45LAN=7498111120R LED-GREEN=LED2PIN LED-YELLOW=LED2PIN G$1=GNDPIN

## WE-RJ45-LAN-10/100/1000BT-SMD-7498111120R (COMPANY-URL: http://www.we-online.de; CREATED-BY: Christin Zierenner; CREATED-DATE: AUG 2012; DATASHEET-URL: http://katalog.we-online.de/kataloge/eisos/media/pdf/7498111120R.pdf; MANUFACTURER: Würth Elektronik eiSos GmbH)  [7498111120R]
1  LED-GREEN:K
2  LED-GREEN:A
3  RJ45LAN:TRD0+
4  RJ45LAN:TRD0-
5  RJ45LAN:TRD1+
6  RJ45LAN:TRD1-
7  RJ45LAN:TRD2+
8  RJ45LAN:TRD2-
9  RJ45LAN:TRD3+
10  RJ45LAN:TRD3-
11  RJ45LAN:VCC  pwr
12  RJ45LAN:GND  pwr
13  LED-YELLOW:K
14  LED-YELLOW:A
Z1  G$1:P$1  pwr
Z2  G$1:P$1  pwr
Z3  G$1:P$1  pwr
Z4  G$1:P$1  pwr

## Footprint 7498111120R (pad centres in mm)
MAX HEIGHT=11.30mm PORTS----1X1 LED --Yes
smd 0.71 x 2.29: 1 -6.63,-3.18; 2 -5.61,-3.18; 3 -4.59,-3.18; 4 -3.57,-3.18; 5 -2.55,-3.18; 6 -1.53,-3.18; 7 -0.51,-3.18; 8 0.51,-3.18; 9 1.53,-3.18; 10 2.55,-3.18; 11 3.57,-3.18; 12 4.59,-3.18; 13 5.61,-3.18; 14 6.63,-3.18; Z3 -8.51,10.2; Z4 8.51,10.2
drill 1.4: Z1 -3.5,0; Z2 3.5,0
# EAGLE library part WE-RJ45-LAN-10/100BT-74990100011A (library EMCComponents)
Order Code 74990100011A Design THT xBase-T 10/100 Base-T Ports 1x1 Application Standard Tab Position UP LED (Left-Right) NONE EMI Fingers No

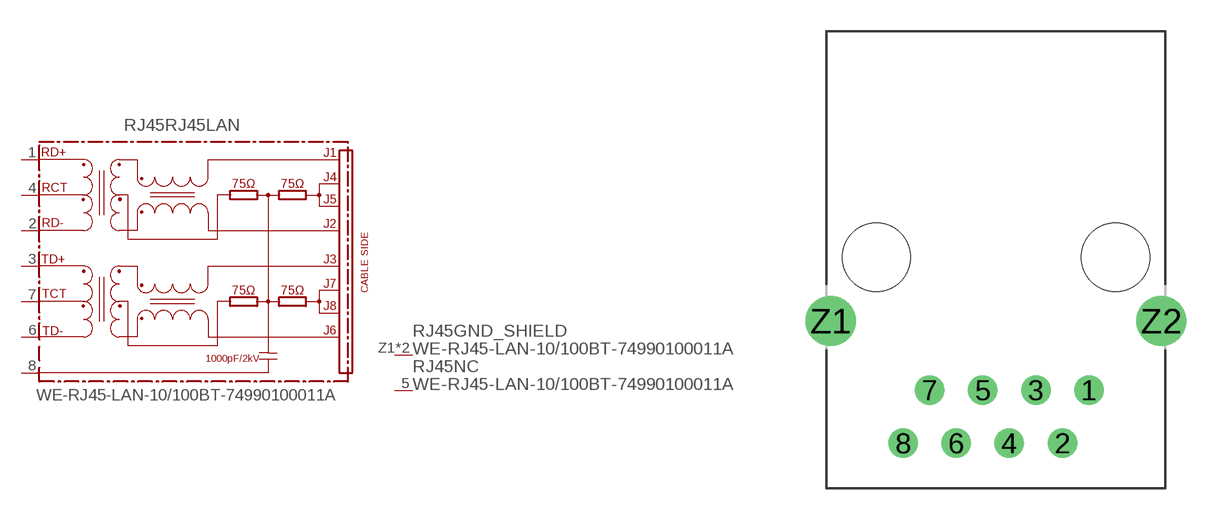
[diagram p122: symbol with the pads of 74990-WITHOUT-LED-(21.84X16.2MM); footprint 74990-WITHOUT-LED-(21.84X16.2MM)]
Designator prefix RJ45; gates RJ45LAN=74990X-THT-10/100-T-RVS GND_SHIELD=GNDPIN NC=NC

## WE-RJ45-LAN-10/100BT-74990100011A (COMPANY-URL: http://www.we-online.de; CREATED-BY: Christin Zierenner; CREATED-DATE: AUG 2012; DATASHEET-URL: http://katalog.we-online.de/kataloge/eisos/media/pdf/74990100011A.pdf; MANUFACTURER: Würth Elektronik eiSos GmbH)  [74990-WITHOUT-LED-(21.84X16.2MM)]
1  RJ45LAN:RD+
2  RJ45LAN:RD-
3  RJ45LAN:TD+
4  RJ45LAN:RCT
5  NC:NC  nc
6  RJ45LAN:TD-
7  RJ45LAN:TCT
8  RJ45LAN:SH  pwr
Z1  GND_SHIELD:P$1  pwr
Z2  GND_SHIELD:P$1  pwr

## Footprint 74990-WITHOUT-LED-(21.84X16.2MM) (pad centres in mm)
MAX HEIGHT=13.74mm PORTS----1X1 LED ----NO
drill 0.9: 1 4.445,-6.35; 2 3.175,-8.89; 3 1.905,-6.35; 4 0.635,-8.89; 5 -0.635,-6.35; 6 -1.905,-8.89; 7 -3.175,-6.35; 8 -4.445,-8.89
drill 1.6: Z1 -7.9,-3.05; Z2 7.9,-3.05
hole 3.25 at 5.715,0
hole 3.25 at -5.715,0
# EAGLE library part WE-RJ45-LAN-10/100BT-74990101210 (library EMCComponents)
Order Code 74990101210 Design THT xBase-T 10/100 Base-T Ports 1x1 Vertical Application Standard Tab Position Vertical LED (Left-Right) Yellow-Green EMI Fingers No

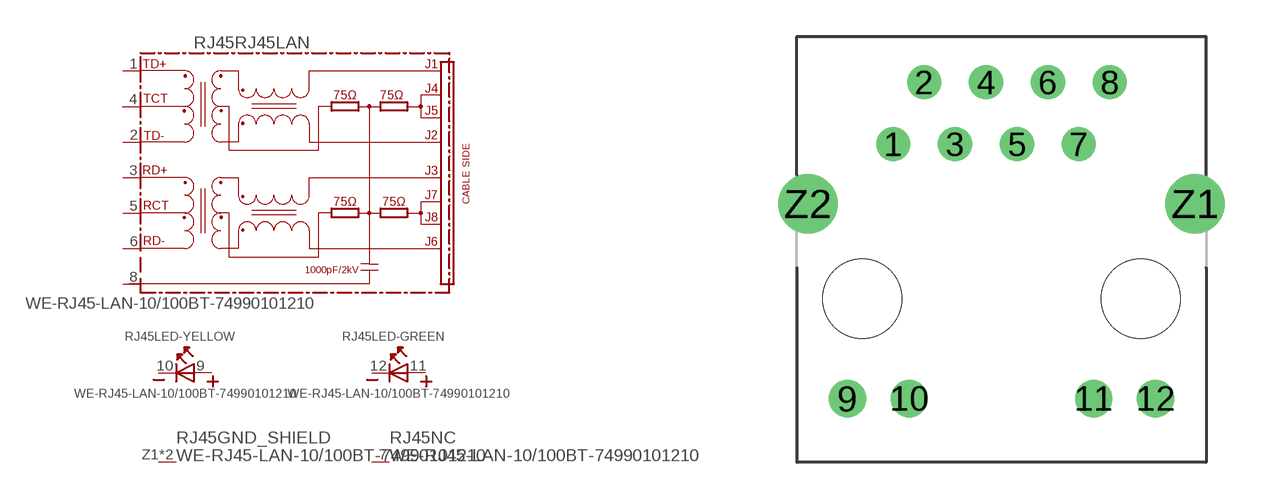
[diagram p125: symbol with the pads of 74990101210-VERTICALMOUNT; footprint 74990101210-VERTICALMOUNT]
Designator prefix RJ45; gates RJ45LAN=74990X-THT-10/100-T LED-YELLOW=LED2PIN LED-GREEN=LED2PIN GND_SHIELD=GND_PIN NC=NC

## WE-RJ45-LAN-10/100BT-74990101210 (COMPANY-URL: http://www.we-online.de; CREATED-BY: Christin Zierenner; CREATED-DATE: AUG 2012; DATASHEET-URL: http://katalog.we-online.de/kataloge/eisos/media/pdf/74990101210.pdf; MANUFACTURER: Würth Elektronik eiSos GmbH)  [74990101210-VERTICALMOUNT]
1  RJ45LAN:TD+
2  RJ45LAN:TD-
3  RJ45LAN:RD+
4  RJ45LAN:TCT
5  RJ45LAN:RCT
6  RJ45LAN:RD-
7  NC:NC  nc
8  RJ45LAN:SH  pwr
9  LED-YELLOW:A
10  LED-YELLOW:K
11  LED-GREEN:A
12  LED-GREEN:K
Z1  GND_SHIELD:P$1  pwr
Z2  GND_SHIELD:P$1  pwr

## Footprint 74990101210-VERTICALMOUNT (pad centres in mm)
MAX HEIGHT=17.50mm VERTICAL MOUNT PORTS----1X1 LED --YES
drill 0.9: 1 -4.445,6.35; 2 -3.175,8.89; 3 -1.905,6.35; 4 -0.635,8.89; 5 0.635,6.35; 6 1.905,8.89; 7 3.175,6.35; 8 4.445,8.89
drill 1.02: 9 -6.325,-4.11; 10 -3.785,-4.11; 11 3.785,-4.11; 12 6.325,-4.11
drill 1.63: Z1 7.95,3.9; Z2 -7.95,3.9
hole 3.25 at -5.715,0
hole 3.25 at 5.715,0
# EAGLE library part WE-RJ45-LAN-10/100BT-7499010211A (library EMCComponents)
Order Code 7499010211A Design THT xBase-T 10/100 Base-T Ports 1x1 Application Standard Tab Position DOWN LED (Left-Right) Green-Yellow EMI Fingers No

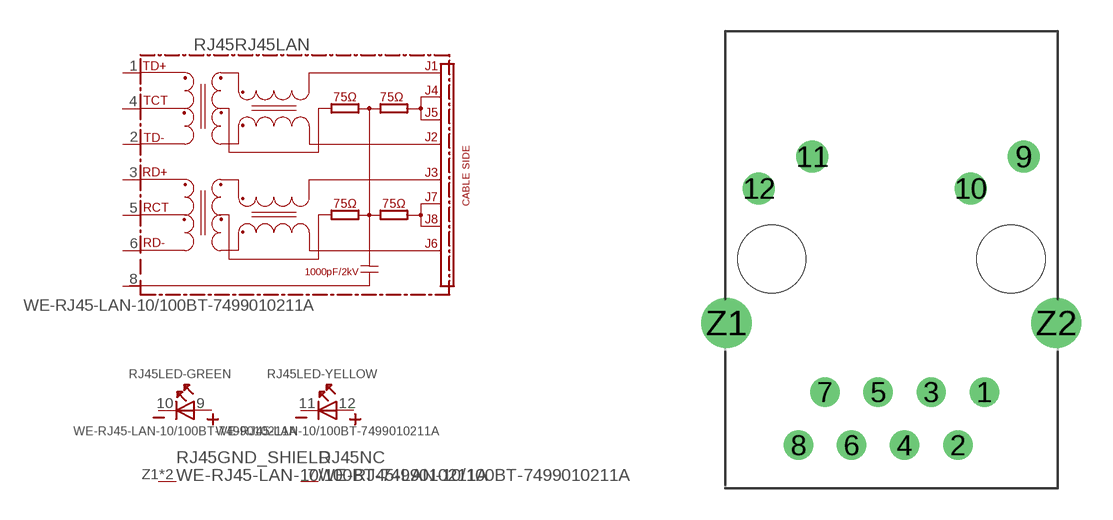
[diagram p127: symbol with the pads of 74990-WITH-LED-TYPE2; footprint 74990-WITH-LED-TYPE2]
Designator prefix RJ45; gates RJ45LAN=74990X-THT-10/100-T LED-GREEN=LED2PIN LED-YELLOW=LED2PIN GND_SHIELD=GND_PIN NC=NC

## WE-RJ45-LAN-10/100BT-7499010211A (COMPANY-URL: http://www.we-online.de; CREATED-BY: Christin Zierenner; CREATED-DATE: AUG 2012; DATASHEET-URL: http://katalog.we-online.de/kataloge/eisos/media/pdf/7499010211A.pdf; MANUFACTURER: Würth Elektronik eiSos GmbH)  [74990-WITH-LED-TYPE2]
1  RJ45LAN:TD+
2  RJ45LAN:TD-
3  RJ45LAN:RD+
4  RJ45LAN:TCT
5  RJ45LAN:RCT
6  RJ45LAN:RD-
7  NC:NC  nc
8  RJ45LAN:SH  pwr
9  LED-GREEN:A
10  LED-GREEN:K
11  LED-YELLOW:K
12  LED-YELLOW:A
Z1  GND_SHIELD:P$1  pwr
Z2  GND_SHIELD:P$1  pwr

## Footprint 74990-WITH-LED-TYPE2 (pad centres in mm)
MAX HEIGHT=13.50mm PORTS----1X1 LED ----YES
drill 0.9: 1 4.445,-6.35; 2 3.175,-8.89; 3 1.905,-6.35; 4 0.635,-8.89; 5 -0.635,-6.35; 6 -1.905,-8.89; 7 -3.175,-6.35; 8 -4.445,-8.89
drill 1.02: 9 6.325,4.9; 10 3.785,3.38; 11 -3.785,4.9; 12 -6.325,3.38
drill 1.6: Z1 -7.875,-3.05; Z2 7.875,-3.05
hole 3.25 at 5.715,0
hole 3.25 at -5.715,0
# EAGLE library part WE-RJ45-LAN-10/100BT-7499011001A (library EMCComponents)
Order Code 7499011001A Design THT xBase-T 10/100 Base-T Ports 1x1 Application Standard Tab Position Down LED (Left-Right) NONE EMI Fingers Yes

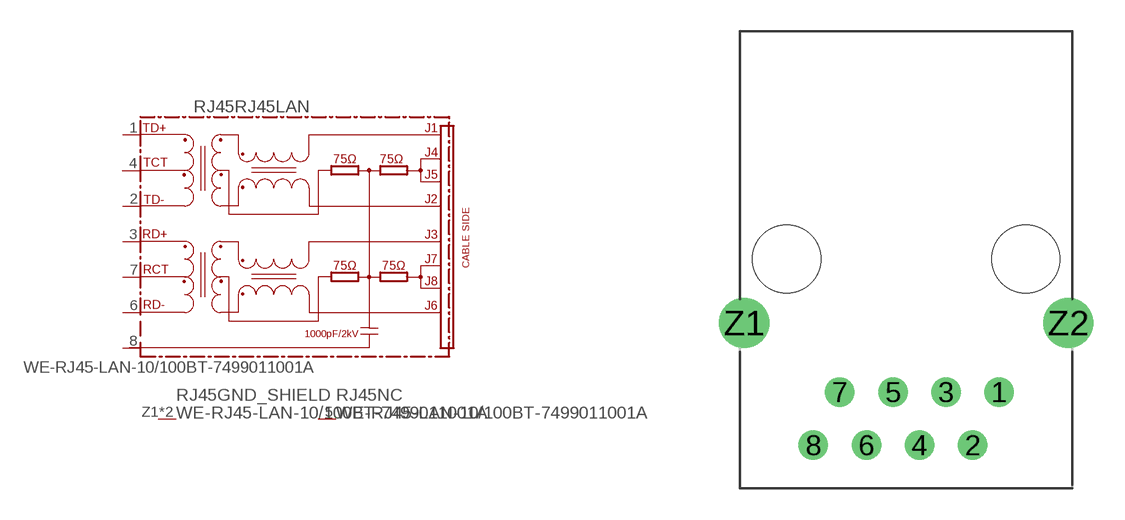
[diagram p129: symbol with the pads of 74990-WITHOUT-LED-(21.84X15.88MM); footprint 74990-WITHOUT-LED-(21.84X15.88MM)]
Designator prefix RJ45; gates RJ45LAN=74990X-THT-10/100-T GND_SHIELD=GND_PIN NC=NC

## WE-RJ45-LAN-10/100BT-7499011001A (COMPANY-URL: http://www.we-online.de; CREATED-BY: Christin Zierenner; CREATED-DATE: AUG 2012; DATASHEET-URL: http://katalog.we-online.de/kataloge/eisos/media/pdf/7499011001A.pdf; MANUFACTURER: Würth Elektronik eiSos GmbH)  [74990-WITHOUT-LED-(21.84X15.88MM)]
1  RJ45LAN:TD+
2  RJ45LAN:TD-
3  RJ45LAN:RD+
4  RJ45LAN:TCT
5  NC:NC  nc
6  RJ45LAN:RD-
7  RJ45LAN:RCT
8  RJ45LAN:SH  pwr
Z1  GND_SHIELD:P$1  pwr
Z2  GND_SHIELD:P$1  pwr

## Footprint 74990-WITHOUT-LED-(21.84X15.88MM) (pad centres in mm)
MAX HEIGHT=13.95mm PORTS----1X1 LED ----NO
drill 0.9: 1 4.445,-6.35; 2 3.175,-8.89; 3 1.905,-6.35; 4 0.635,-8.89; 5 -0.635,-6.35; 6 -1.905,-8.89; 7 -3.175,-6.35; 8 -4.445,-8.89
drill 1.6: Z1 -7.745,-3.05; Z2 7.745,-3.05
hole 3.25 at 5.715,0
hole 3.25 at -5.715,0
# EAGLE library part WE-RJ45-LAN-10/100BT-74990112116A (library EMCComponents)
Order Code 74990112116A Design THT xBase-T 10/100 Base-T Ports 1x1 Application Standard Tab Position UP LED (Left-Right) Green-Yellow EMI Fingers Yes

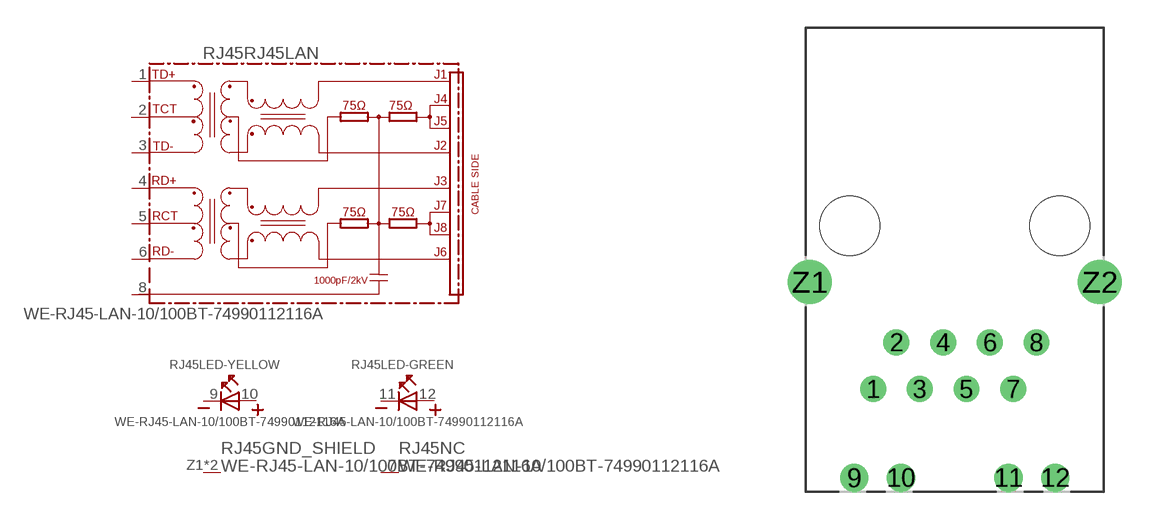
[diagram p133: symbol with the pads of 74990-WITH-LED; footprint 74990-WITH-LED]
Designator prefix RJ45; gates RJ45LAN=74990X-THT-10/100-T LED-GREEN=LED2PIN LED-YELLOW=LED2PIN GND_SHIELD=GND_PIN NC=NC

## WE-RJ45-LAN-10/100BT-74990112116A (COMPANY-URL: http://www.we-online.de; CREATED-BY: Christin Zierenner; CREATED-DATE: AUG 2012; DATASHEET-URL: http://katalog.we-online.de/kataloge/eisos/media/pdf/74990112116A.pdf; MANUFACTURER: Würth Elektronik eiSos GmbH)  [74990-WITH-LED]
1  RJ45LAN:TD+
2  RJ45LAN:TCT
3  RJ45LAN:TD-
4  RJ45LAN:RD+
5  RJ45LAN:RCT
6  RJ45LAN:RD-
7  NC:NC  nc
8  RJ45LAN:SH  pwr
9  LED-YELLOW:K
10  LED-YELLOW:A
11  LED-GREEN:K
12  LED-GREEN:A
Z1  GND_SHIELD:P$1  pwr
Z2  GND_SHIELD:P$1  pwr

## Footprint 74990-WITH-LED (pad centres in mm)
MAX HEIGHT=13.50mm PORTS----1X1 LED -YES
drill 0.9: 1 -4.445,-8.89; 2 -3.175,-6.35; 3 -1.905,-8.89; 4 -0.635,-6.35; 5 0.635,-8.89; 6 1.905,-6.35; 7 3.175,-8.89; 8 4.445,-6.35
drill 1.02: 9 -5.465,-13.72; 10 -2.925,-13.72; 11 2.925,-13.72; 12 5.465,-13.72
drill 1.6: Z1 -7.9,-3.05; Z2 7.9,-3.05
hole 3.25 at -5.715,0
hole 3.25 at 5.715,0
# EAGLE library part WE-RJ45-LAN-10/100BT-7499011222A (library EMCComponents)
Order Code 7499011222A Design THT xBase-T 10/100 Base-T Ports 1x1 Application Standard Tab Position DOWN LED (Left-Right) Green-Green EMI Fingers Yes

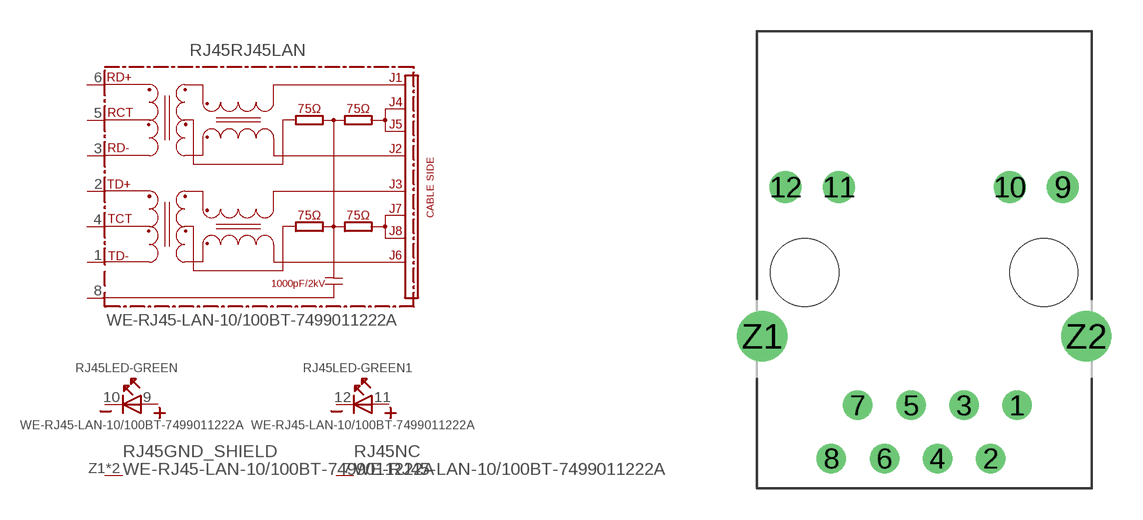
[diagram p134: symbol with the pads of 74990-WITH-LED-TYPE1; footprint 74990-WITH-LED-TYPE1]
Designator prefix RJ45; gates RJ45LAN=74990X-THT-10/100-T-RVS LED-GREEN=LED2PIN LED-GREEN1=LED2PIN GND_SHIELD=GND_PIN NC=NC

## WE-RJ45-LAN-10/100BT-7499011222A (COMPANY-URL: http://www.we-online.de; CREATED-BY: Christin Zierenner; CREATED-DATE: AUG 2012; DATASHEET-URL: http://katalog.we-online.de/kataloge/eisos/media/pdf/7499011222A.pdf; MANUFACTURER: Würth Elektronik eiSos GmbH)  [74990-WITH-LED-TYPE1]
1  RJ45LAN:TD-
2  RJ45LAN:TD+
3  RJ45LAN:RD-
4  RJ45LAN:TCT
5  RJ45LAN:RCT
6  RJ45LAN:RD+
7  NC:NC  nc
8  RJ45LAN:SH  pwr
9  LED-GREEN:A
10  LED-GREEN:K
11  LED-GREEN1:A
12  LED-GREEN1:K
Z1  GND_SHIELD:P$1  pwr
Z2  GND_SHIELD:P$1  pwr

## Footprint 74990-WITH-LED-TYPE1 (pad centres in mm)
MAX HEIGHT=13.90mm PORTS----1X1 LED --YES
drill 0.9: 1 4.445,-6.35; 2 3.175,-8.89; 3 1.905,-6.35; 4 0.635,-8.89; 5 -0.635,-6.35; 6 -1.905,-8.89; 7 -3.175,-6.35; 8 -4.445,-8.89
drill 1.02: 9 6.625,4.08; 10 4.085,4.08; 11 -4.085,4.08; 12 -6.625,4.08
drill 1.6: Z1 -7.745,-3.05; Z2 7.745,-3.05
hole 3.25 at 5.715,0
hole 3.25 at -5.715,0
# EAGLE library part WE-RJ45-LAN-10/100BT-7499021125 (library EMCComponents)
Order Code 7499021125 Design THT xBase-T 10/100 Base-T Ports 1x2 HORIZONTAL Application Standard Tab Position DOWN LED (Left-Right) YELLOW-GREEN EMI Fingers Yes

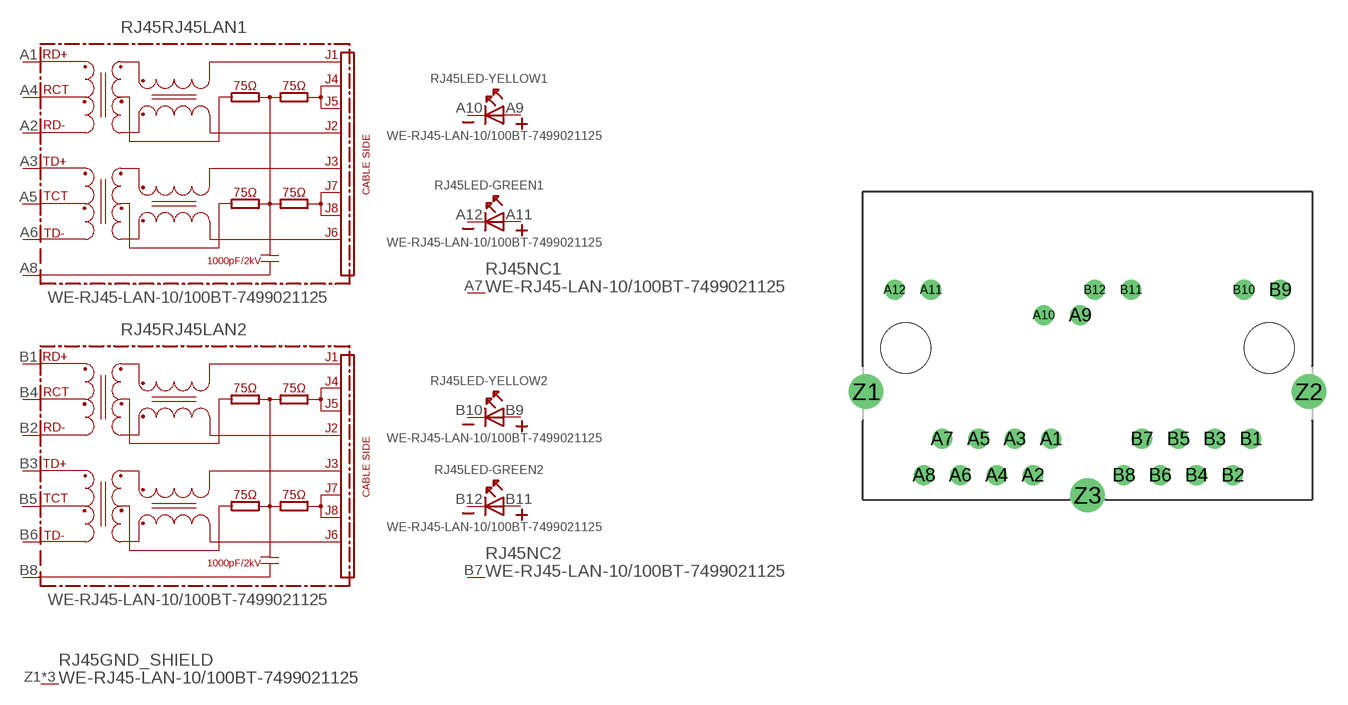
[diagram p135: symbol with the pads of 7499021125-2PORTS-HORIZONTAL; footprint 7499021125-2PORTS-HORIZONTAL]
Designator prefix RJ45; gates RJ45LAN1=74990X-THT-10/100-T-RVS LED-YELLOW1=LED2PIN LED-GREEN1=LED2PIN RJ45LAN2=74990X-THT-10/100-T-RVS LED-YELLOW2=LED2PIN LED-GREEN2=LED2PIN GND_SHIELD=GND_PIN NC1=NC NC2=NC

## WE-RJ45-LAN-10/100BT-7499021125 (COMPANY-URL: http://www.we-online.de; CREATED-BY: Christin Zierenner; CREATED-DATE: AUG 2012; DATASHEET-URL: http://katalog.we-online.de/kataloge/eisos/media/pdf/7499021125.pdf; MANUFACTURER: Würth Elektronik eiSos GmbH)  [7499021125-2PORTS-HORIZONTAL]
A1  RJ45LAN1:RD+
A2  RJ45LAN1:RD-
A3  RJ45LAN1:TD+
A4  RJ45LAN1:RCT
A5  RJ45LAN1:TCT
A6  RJ45LAN1:TD-
A7  NC1:NC  nc
A8  RJ45LAN1:SH  pwr
A9  LED-YELLOW1:A
A10  LED-YELLOW1:K
A11  LED-GREEN1:A
A12  LED-GREEN1:K
B1  RJ45LAN2:RD+
B2  RJ45LAN2:RD-
B3  RJ45LAN2:TD+
B4  RJ45LAN2:RCT
B5  RJ45LAN2:TCT
B6  RJ45LAN2:TD-
B7  NC2:NC  nc
B8  RJ45LAN2:SH  pwr
B9  LED-YELLOW2:A
B10  LED-YELLOW2:K
B11  LED-GREEN2:A
B12  LED-GREEN2:K
Z1  GND_SHIELD:P$1  pwr
Z2  GND_SHIELD:P$1  pwr
Z3  GND_SHIELD:P$1  pwr

## Footprint 7499021125-2PORTS-HORIZONTAL (pad centres in mm)
MAX HEIGHT=13.50mm PORTS----1X2 HORIZONTAL LED --YES
drill 0.9: A1 -2.54,-6.35; A2 -3.81,-8.89; A3 -5.08,-6.35; A4 -6.35,-8.89; A5 -7.62,-6.35; A6 -8.89,-8.89; A7 -10.16,-6.35; A8 -11.43,-8.89; A9 -0.51,2.29; A10 -3.05,2.29; A11 -10.93,4.06; A12 -13.47,4.06; B1 11.43,-6.35; B2 10.16,-8.89; B3 8.89,-6.35; B4 7.62,-8.89; B5 6.35,-6.35; B6 5.08,-8.89; B7 3.81,-6.35; B8 2.54,-8.89; B9 13.47,4.06; B10 10.93,4.06; B11 3.05,4.06; B12 0.51,4.06
drill 1.6: Z1 -15.465,-3.05; Z2 15.465,-3.05; Z3 0,-10.29
hole 3.52 at -12.7,0
hole 3.52 at 12.7,0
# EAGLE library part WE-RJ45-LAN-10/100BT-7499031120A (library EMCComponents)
Order Code 7499031120A Design THT xBase-T 10/100 Base-T Ports 1x4 HORIZONTAL Application Standard Tab Position DOWN LED (Left-Right) YELLOW-GREEN EMI Fingers Yes

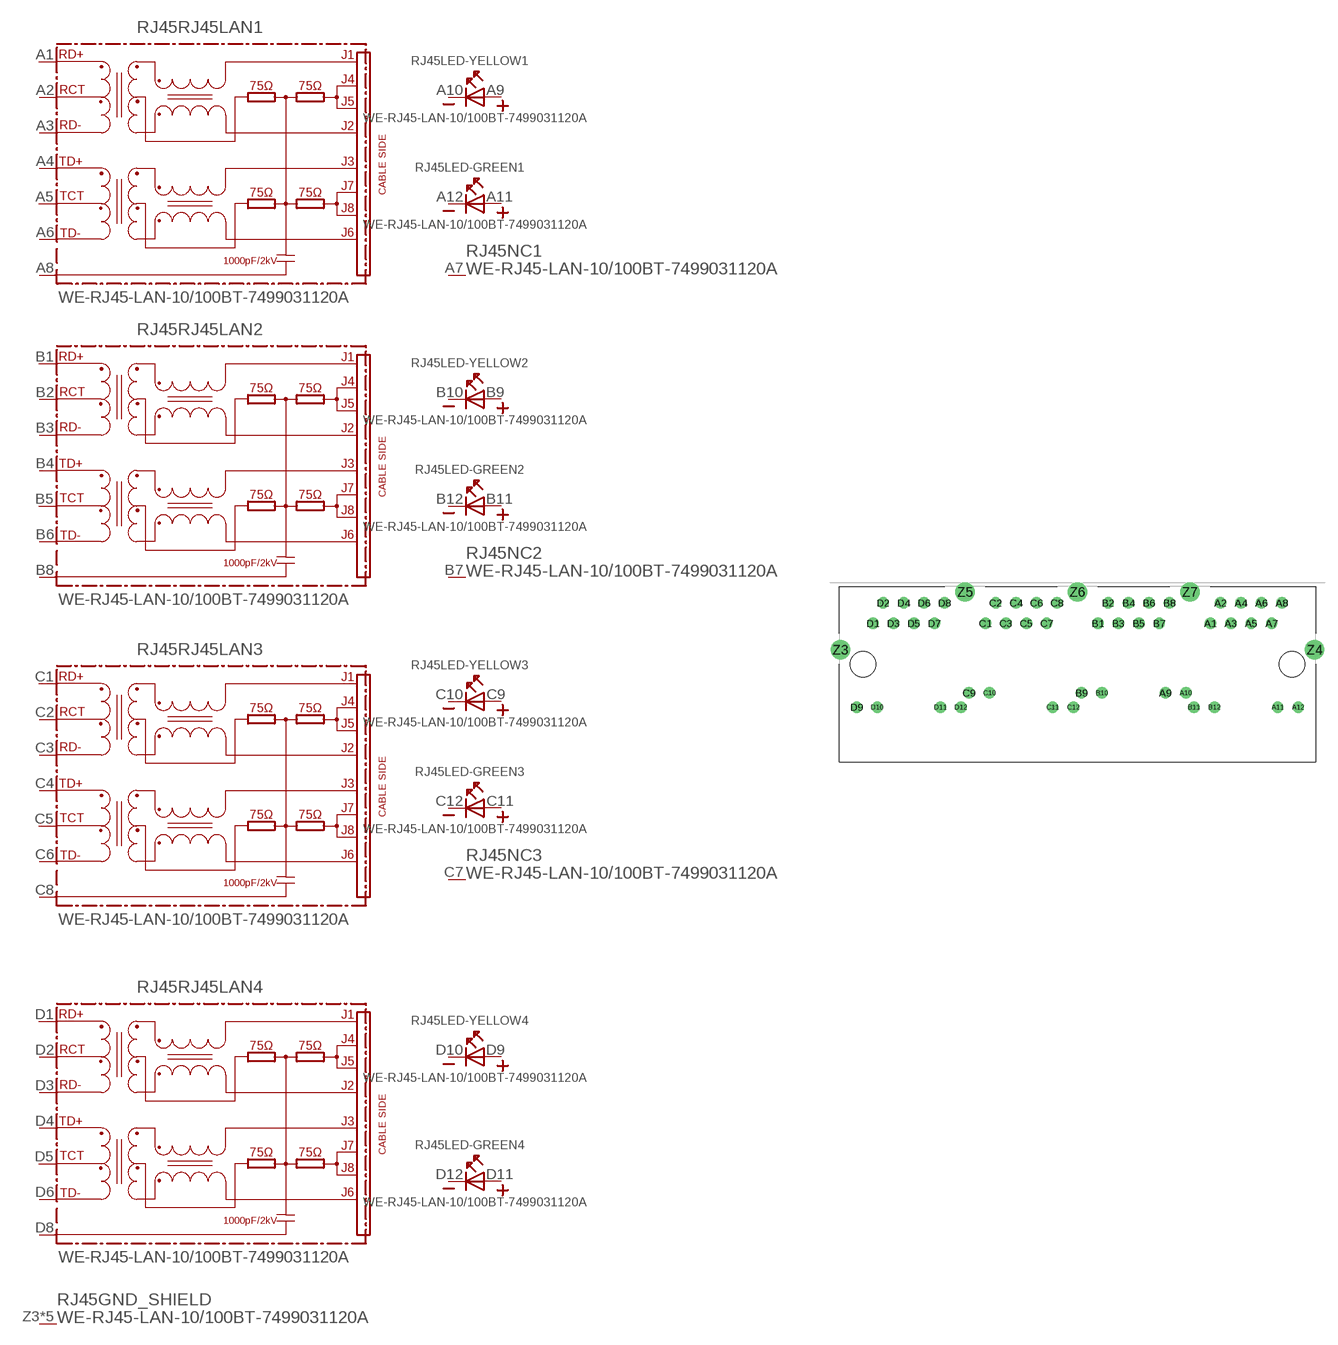
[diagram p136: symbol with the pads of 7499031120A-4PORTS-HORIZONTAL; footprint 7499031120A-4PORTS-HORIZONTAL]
Designator prefix RJ45; gates RJ45LAN1=74990X-THT-10/100-T-RVS RJ45LAN2=74990X-THT-10/100-T-RVS RJ45LAN3=74990X-THT-10/100-T-RVS RJ45LAN4=74990X-THT-10/100-T-RVS LED-YELLOW1=LED2PIN LED-GREEN1=LED2PIN LED-YELLOW2=LED2PIN LED-GREEN2=LED2PIN LED-YELLOW3=LED2PIN LED-GREEN3=LED2PIN LED-YELLOW4=LED2PIN LED-GREEN4=LED2PIN GND_SHIELD=GND_PIN NC1=NC NC2=NC NC3=NC NC4=NC

## WE-RJ45-LAN-10/100BT-7499031120A (COMPANY-URL: http://www.we-online.de; CREATED-BY: Christin Zierenner; CREATED-DATE: AUG 2012; DATASHEET-URL: http://katalog.we-online.de/kataloge/eisos/media/pdf/7499031120A.pdf; MANUFACTURER: Würth Elektronik eiSos GmbH)  [7499031120A-4PORTS-HORIZONTAL]
A1  RJ45LAN1:RD+
A2  RJ45LAN1:RCT
A3  RJ45LAN1:RD-
A4  RJ45LAN1:TD+
A5  RJ45LAN1:TCT
A6  RJ45LAN1:TD-
A7  NC1:NC  nc
A8  RJ45LAN1:SH  pwr
A9  LED-YELLOW1:A
A10  LED-YELLOW1:K
A11  LED-GREEN1:A
A12  LED-GREEN1:K
B1  RJ45LAN2:RD+
B2  RJ45LAN2:RCT
B3  RJ45LAN2:RD-
B4  RJ45LAN2:TD+
B5  RJ45LAN2:TCT
B6  RJ45LAN2:TD-
B7  NC2:NC  nc
B8  RJ45LAN2:SH  pwr
B9  LED-YELLOW2:A
B10  LED-YELLOW2:K
B11  LED-GREEN2:A
B12  LED-GREEN2:K
C1  RJ45LAN3:RD+
C2  RJ45LAN3:RCT
C3  RJ45LAN3:RD-
C4  RJ45LAN3:TD+
C5  RJ45LAN3:TCT
C6  RJ45LAN3:TD-
C7  NC3:NC  nc
C8  RJ45LAN3:SH  pwr
C9  LED-YELLOW3:A
C10  LED-YELLOW3:K
C11  LED-GREEN3:A
C12  LED-GREEN3:K
D1  RJ45LAN4:RD+
D2  RJ45LAN4:RCT
D3  RJ45LAN4:RD-
D4  RJ45LAN4:TD+
D5  RJ45LAN4:TCT
D6  RJ45LAN4:TD-
D7  NC4:NC  nc
D8  RJ45LAN4:SH  pwr
D9  LED-YELLOW4:A
D10  LED-YELLOW4:K
D11  LED-GREEN4:A
D12  LED-GREEN4:K
Z3  GND_SHIELD:P$1  pwr
Z4  GND_SHIELD:P$1  pwr
Z5  GND_SHIELD:P$1  pwr
Z6  GND_SHIELD:P$1  pwr
Z7  GND_SHIELD:P$1  pwr

## Footprint 7499031120A-4PORTS-HORIZONTAL (pad centres in mm)
MAX HEIGHT=13.50mm PORTS----1X4 HORIZONTAL LED --YES
drill 0.9: A1 16.51,6.35; A2 17.78,8.89; A3 19.05,6.35; A4 20.32,8.89; A5 21.59,6.35; A6 22.86,8.89; A7 24.13,6.35; A8 25.4,8.89; A9 10.92,-2.29; A10 13.46,-2.29; A11 24.88,-4.06; A12 27.42,-4.06; B1 2.54,6.35; B2 3.81,8.89; B3 5.08,6.35; B4 6.35,8.89; B5 7.62,6.35; B6 8.89,8.89; B7 10.16,6.35; B8 11.43,8.89; B9 0.51,-2.29; B10 3.05,-2.29; B11 14.48,-4.06; B12 17.02,-4.06; C1 -11.43,6.35; C2 -10.16,8.89; C3 -8.89,6.35; C4 -7.62,8.89; C5 -6.35,6.35; C6 -5.08,8.89; C7 -3.81,6.35; C8 -2.54,8.89; C9 -13.46,-2.29; C10 -10.92,-2.29; C11 -3.07,-4.06; C12 -0.51,-4.06; D1 -25.4,6.35; D2 -24.13,8.89; D3 -22.86,6.35; D4 -21.59,8.89; D5 -20.32,6.35; D6 -19.05,8.89; D7 -17.78,6.35; D8 -16.51,8.89; D9 -27.42,-4.06; D10 -24.88,-4.06; D11 -17.02,-4.06; D12 -14.48,-4.06
drill 1.6: Z3 -29.455,3.05; Z4 29.455,3.05; Z5 -13.97,10.24; Z6 0,10.24; Z7 13.97,10.24
hole 3.18 at -26.67,1.27
hole 3.18 at 26.67,1.27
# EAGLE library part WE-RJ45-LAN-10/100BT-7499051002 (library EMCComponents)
Order Code 7499051002 Design THT xBase-T 10/100 Base-T Ports 1x2 STACKED Application Standard Tab Position UP & DOWN LED (Left-Right) NONE EMI Fingers Yes

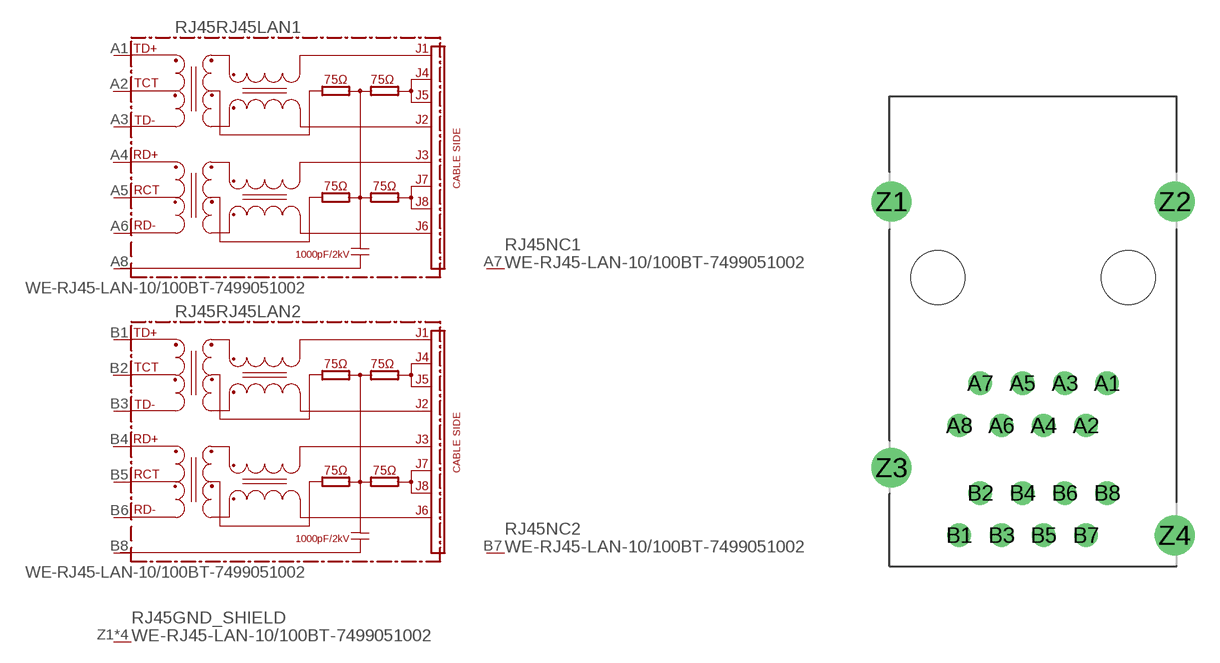
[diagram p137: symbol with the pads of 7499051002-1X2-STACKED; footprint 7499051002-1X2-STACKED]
Designator prefix RJ45; gates RJ45LAN1=74990X-THT-10/100-T RJ45LAN2=74990X-THT-10/100-T GND_SHIELD=GND_PIN NC1=NC NC2=NC

## WE-RJ45-LAN-10/100BT-7499051002 (COMPANY-URL: http://www.we-online.de; CREATED-BY: Christin Zierenner; CREATED-DATE: AUG 2012; DATASHEET-URL: http://katalog.we-online.de/kataloge/eisos/media/pdf/7499051002.pdf; MANUFACTURER: Würth Elektronik eiSos GmbH)  [7499051002-1X2-STACKED]
A1  RJ45LAN1:TD+
A2  RJ45LAN1:TCT
A3  RJ45LAN1:TD-
A4  RJ45LAN1:RD+
A5  RJ45LAN1:RCT
A6  RJ45LAN1:RD-
A7  NC1:NC  nc
A8  RJ45LAN1:SH  pwr
B1  RJ45LAN2:TD+
B2  RJ45LAN2:TCT
B3  RJ45LAN2:TD-
B4  RJ45LAN2:RD+
B5  RJ45LAN2:RCT
B6  RJ45LAN2:RD-
B7  NC2:NC  nc
B8  RJ45LAN2:SH  pwr
Z1  GND_SHIELD:P$1  pwr
Z2  GND_SHIELD:P$1  pwr
Z3  GND_SHIELD:P$1  pwr
Z4  GND_SHIELD:P$1  pwr

## Footprint 7499051002-1X2-STACKED (pad centres in mm)
MAX HEIGHT=25.20mm PORTS----1X2 STACKED LED --No
drill 0.9: A1 4.445,-6.35; A2 3.175,-8.89; A3 1.905,-6.35; A4 0.635,-8.89; A5 -0.635,-6.35; A6 -1.905,-8.89; A7 -3.175,-6.35; A8 -4.445,-8.89; B1 -4.445,-15.49; B2 -3.175,-12.95; B3 -1.905,-15.49; B4 -0.635,-12.95; B5 0.635,-15.49; B6 1.905,-12.95; B7 3.175,-15.49; B8 4.445,-12.95
drill 1.6: Z1 -8.51,4.57; Z2 8.51,4.57; Z3 -8.51,-11.43; Z4 8.51,-15.5
hole 3.25 at 5.715,0
hole 3.25 at -5.715,0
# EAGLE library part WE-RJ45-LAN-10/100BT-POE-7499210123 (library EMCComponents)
Order Code 7499210123 Design THT xBase-T 10/100 Base-T PoE Ports 1x1 Application PoE Tab Position VERTICAL LED (Left-Right) YELLOW-GREEN EMI Fingers No

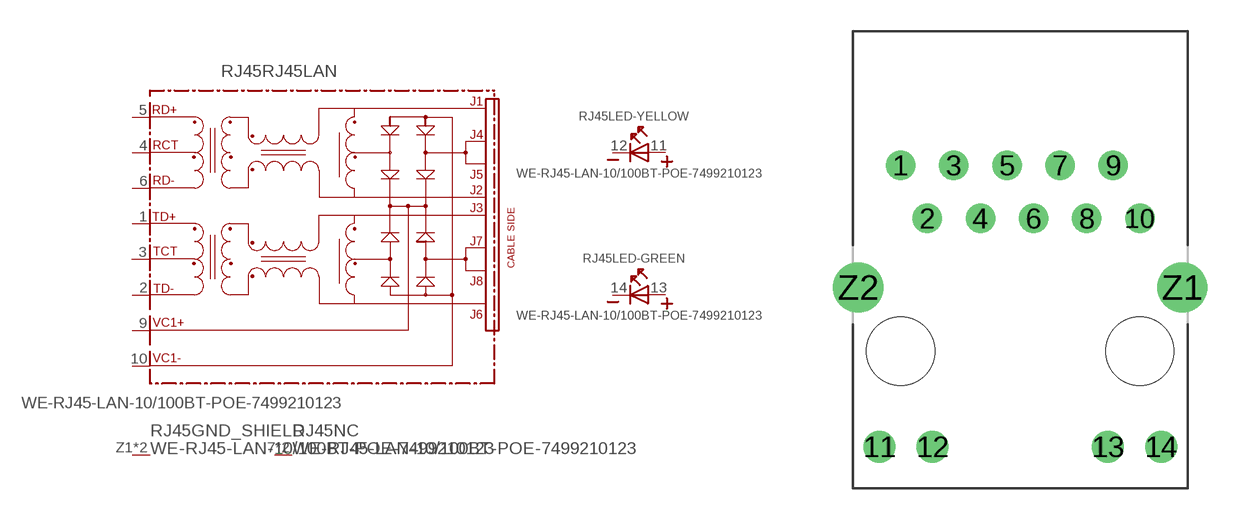
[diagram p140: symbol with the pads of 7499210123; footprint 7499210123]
Designator prefix RJ45; gates LED-YELLOW=LED2PIN LED-GREEN=LED2PIN RJ45LAN=749921-THT-POE-RVS GND_SHIELD=GND_PIN NC=NC

## WE-RJ45-LAN-10/100BT-POE-7499210123 (COMPANY-URL: http://www.we-online.de; CREATED-BY: Christin Zierenner; CREATED-DATE: AUG 2012; DATASHEET-URL: http://katalog.we-online.de/kataloge/eisos/media/pdf/7499210123.pdf; MANUFACTURER: Würth Elektronik eiSos GmbH)  [7499210123]
1  RJ45LAN:TD+
2  RJ45LAN:TD-
3  RJ45LAN:TCT
4  RJ45LAN:RCT
5  RJ45LAN:RD+
6  RJ45LAN:RD-
7  NC:NC  nc
8  NC:NC  nc
9  RJ45LAN:VC1+  pwr
10  RJ45LAN:VC1-  pwr
11  LED-YELLOW:A
12  LED-YELLOW:K
13  LED-GREEN:A
14  LED-GREEN:K
Z1  GND_SHIELD:P$1  pwr
Z2  GND_SHIELD:P$1  pwr

## Footprint 7499210123 (pad centres in mm)
MAX HEIGHT=16.90mm PORTS----1X1 LED ---YES
drill 0.9: 1 -5.715,8.89; 2 -4.445,6.35; 3 -3.175,8.89; 4 -1.905,6.35; 5 -0.635,8.89; 6 0.635,6.35; 7 1.905,8.89; 8 3.175,6.35; 9 4.445,8.89; 10 5.715,6.35
drill 1.02: 11 -6.73,-4.57; 12 -4.19,-4.57; 13 4.19,-4.57; 14 6.73,-4.57
drill 1.6: Z1 7.745,3.05; Z2 -7.745,3.05
hole 3.25 at -5.715,0
hole 3.25 at 5.715,0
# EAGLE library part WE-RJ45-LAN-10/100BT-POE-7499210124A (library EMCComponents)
Order Code 7499210124A Design THT xBase-T 10/100 Base-T PoE Ports 1x1 Application PoE Tab Position UP LED (Left-Right) YELLOW-GREEN EMI Fingers No

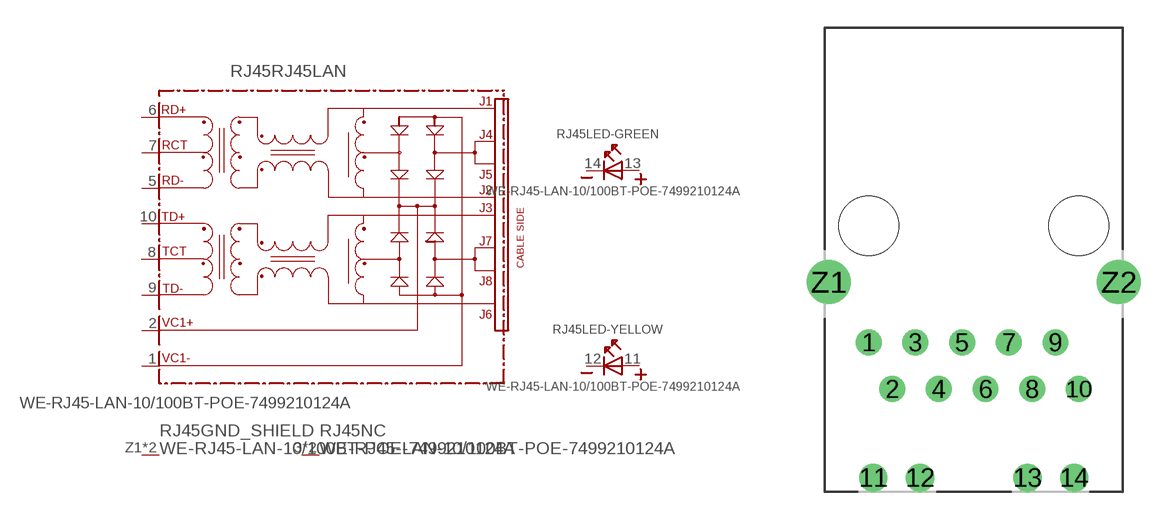
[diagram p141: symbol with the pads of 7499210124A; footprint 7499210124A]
Designator prefix RJ45; gates RJ45LAN=749921-THT-POE-RVS LED-GREEN=LED2PIN LED-YELLOW=LED2PIN GND_SHIELD=GND_PIN NC=NC

## WE-RJ45-LAN-10/100BT-POE-7499210124A (COMPANY-URL: http://www.we-online.de; CREATED-BY: Christin Zierenner; CREATED-DATE: AUG 2012; DATASHEET-URL: http://katalog.we-online.de/kataloge/eisos/media/pdf/7499210124A.pdf; MANUFACTURER: Würth Elektronik eiSos GmbH)  [7499210124A]
1  RJ45LAN:VC1-  pwr
2  RJ45LAN:VC1+  pwr
3  NC:NC  nc
4  NC:NC  nc
5  RJ45LAN:RD-
6  RJ45LAN:RD+
7  RJ45LAN:RCT
8  RJ45LAN:TCT
9  RJ45LAN:TD-
10  RJ45LAN:TD+
11  LED-YELLOW:A
12  LED-YELLOW:K
13  LED-GREEN:A
14  LED-GREEN:K
Z1  GND_SHIELD:P$1  pwr
Z2  GND_SHIELD:P$1  pwr

## Footprint 7499210124A (pad centres in mm)
MAX HEIGHT=13.50mm PORTS----1X1 LED --YES
drill 0.9: 1 -5.715,-6.35; 2 -4.445,-8.89; 3 -3.175,-6.35; 4 -1.905,-8.89; 5 -0.635,-6.35; 6 0.635,-8.89; 7 1.905,-6.35; 8 3.175,-8.89; 9 4.445,-6.35; 10 5.715,-8.89
drill 1.02: 11 -5.465,-13.72; 12 -2.925,-13.72; 13 2.925,-13.72; 14 5.465,-13.72
drill 1.6: Z1 -7.9,-3.05; Z2 7.9,-3.05
hole 3.25 at 5.715,0
hole 3.25 at -5.715,0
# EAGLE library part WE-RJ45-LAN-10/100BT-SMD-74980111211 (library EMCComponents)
Order Code 74980111211 Design SMD xBase-T 10/100 Base-T Ports 1x1 Application Standard Tab Position Up LED (Left-Right) YELLOW-GREEN EMI Fingers Yes

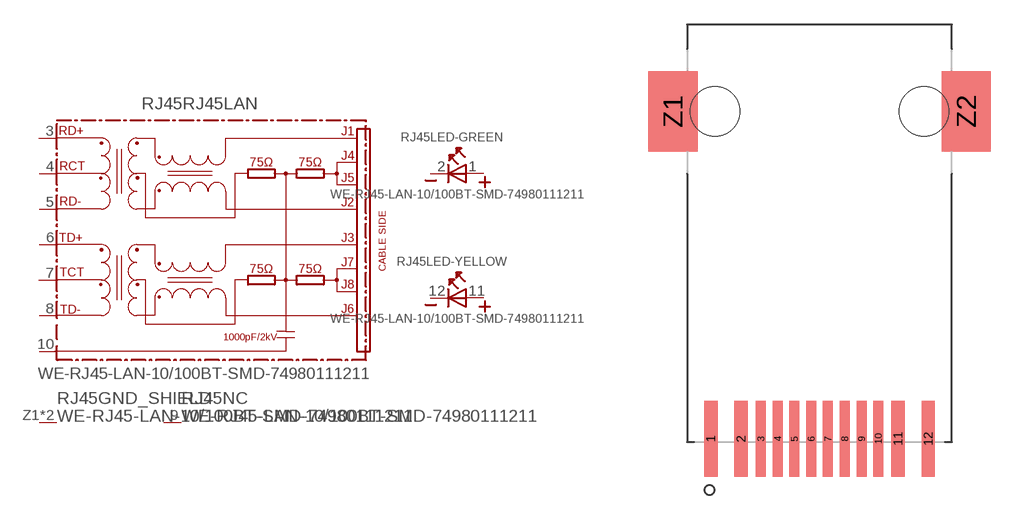
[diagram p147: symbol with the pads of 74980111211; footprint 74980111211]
Designator prefix RJ45; gates RJ45LAN=74990X-THT-10/100-T-RVS LED-GREEN=LED2PIN LED-YELLOW=LED2PIN GND_SHIELD=GND_PIN NC=NC

## WE-RJ45-LAN-10/100BT-SMD-74980111211 (COMPANY-URL: http://www.we-online.de; CREATED-BY: Christin Zierenner; CREATED-DATE: AUG 2012; DATASHEET-URL: http://katalog.we-online.de/kataloge/eisos/media/pdf/74980111211.pdf; MANUFACTURER: Würth Elektronik eiSos GmbH)  [74980111211]
1  LED-GREEN:A
2  LED-GREEN:K
3  RJ45LAN:RD+
4  RJ45LAN:RCT
5  RJ45LAN:RD-
6  RJ45LAN:TD+
7  RJ45LAN:TCT
8  RJ45LAN:TD-
9  NC:NC  nc
10  RJ45LAN:SH  pwr
11  LED-YELLOW:A
12  LED-YELLOW:K
Z1  GND_SHIELD:P$1  pwr
Z2  GND_SHIELD:P$1  pwr

## Footprint 74980111211 (pad centres in mm)
MAX HEIGHT=13.61mm PORTS----1X1 LED --Yes
smd 0.81 x 4.6: 1 -6.61,-19.92; 2 -4.77,-19.92; 11 4.77,-19.92; 12 6.61,-19.92
smd 0.61 x 4.6: 3 -3.57,-19.92; 4 -2.55,-19.92; 5 -1.53,-19.92; 6 -0.51,-19.92; 7 0.51,-19.92; 8 1.53,-19.92; 9 2.55,-19.92; 10 3.57,-19.92
smd 3 x 4.9: Z1 -8.92,0; Z2 8.92,0
hole 3 at 6.35,0
hole 3 at -6.35,0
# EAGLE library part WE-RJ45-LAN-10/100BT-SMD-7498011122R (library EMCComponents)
Order Code 7498011122R Design SMD xBase-T 10/100 Base-T Ports 1x1 Application Standard Tab Position Up LED (Left-Right) YELLOW-GREEN EMI Fingers Yes

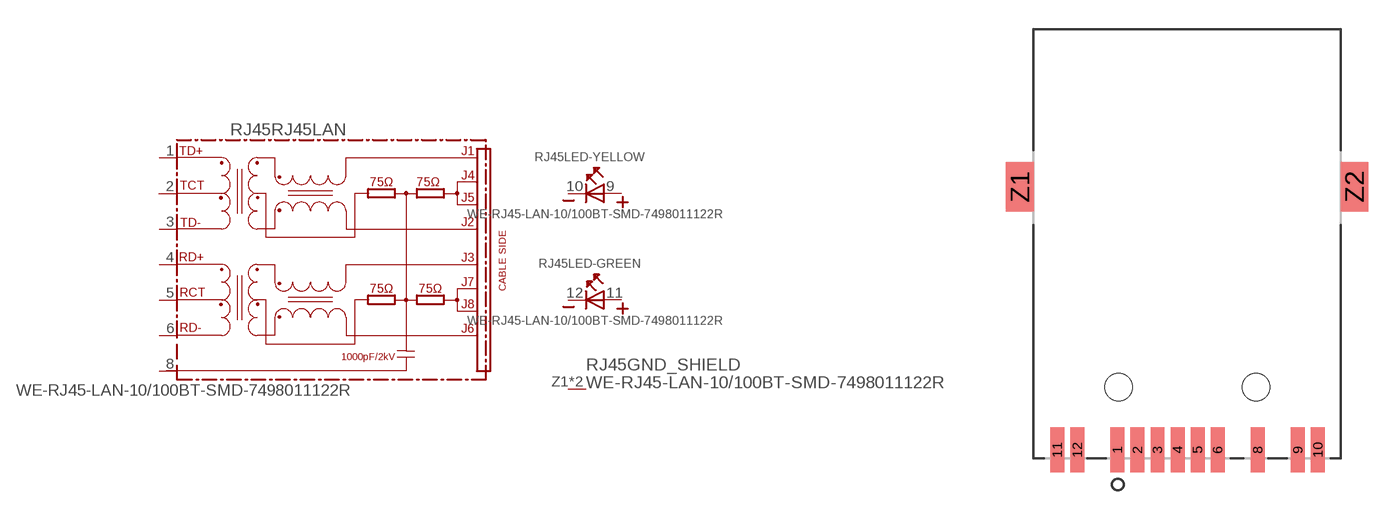
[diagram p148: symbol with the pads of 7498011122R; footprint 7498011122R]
Designator prefix RJ45; gates RJ45LAN=74990X-THT-10/100-T LED-YELLOW=LED2PIN LED-GREEN=LED2PIN GND_SHIELD=GND_PIN

## WE-RJ45-LAN-10/100BT-SMD-7498011122R (COMPANY-URL: http://www.we-online.de; CREATED-BY: Christin Zierenner; CREATED-DATE: AUG 2012; DATASHEET-URL: http://katalog.we-online.de/kataloge/eisos/media/pdf/7498011122R.pdf; MANUFACTURER: Würth Elektronik eiSos GmbH)  [7498011122R]
1  RJ45LAN:TD+
2  RJ45LAN:TCT
3  RJ45LAN:TD-
4  RJ45LAN:RD+
5  RJ45LAN:RCT
6  RJ45LAN:RD-
8  RJ45LAN:SH  pwr
9  LED-YELLOW:A
10  LED-YELLOW:K
11  LED-GREEN:A
12  LED-GREEN:K
Z1  GND_SHIELD:P$1  pwr
Z2  GND_SHIELD:P$1  pwr

## Footprint 7498011122R (pad centres in mm)
MAX HEIGHT=11.30mm PORTS----1X1 LED --Yes
smd 0.71 x 2.29: 1 -3.545,-3.18; 2 -2.525,-3.18; 3 -1.505,-3.18; 4 -0.485,-3.18; 5 0.535,-3.18; 6 1.555,-3.18; 8 3.595,-3.18; 9 5.635,-3.18; 10 6.655,-3.18; 11 -6.605,-3.18; 12 -5.585,-3.18
smd 1.4 x 2.54: Z1 -8.51,10.2; Z2 8.51,10.2
hole 1.4 at -3.5,0
hole 1.4 at 3.5,0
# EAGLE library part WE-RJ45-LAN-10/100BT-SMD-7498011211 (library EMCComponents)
Order Code 7498011211 Design SMD xBase-T 10/100 Base-T Ports 1x1 Application Standard Tab Position DOWN LED (Left-Right) GREEN-YELLOW EMI Fingers Yes

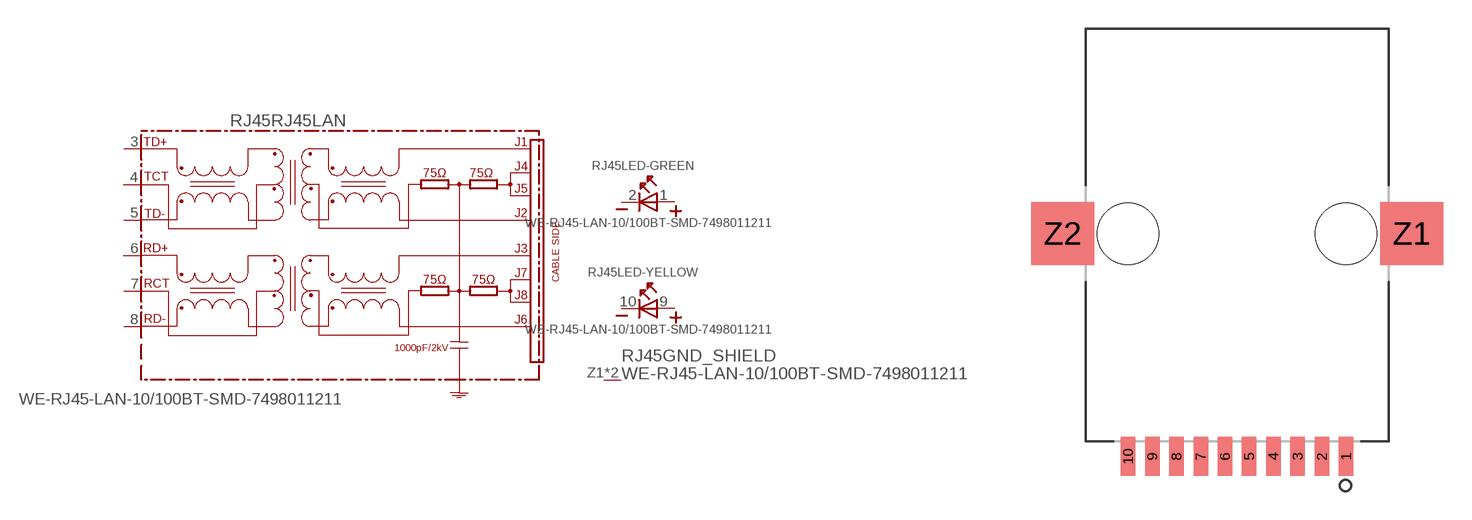
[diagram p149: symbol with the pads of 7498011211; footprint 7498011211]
Designator prefix RJ45; gates RJ45LAN=7498011211 LED-GREEN=LED2PIN LED-YELLOW=LED2PIN GND_SHIELD=GNDPIN

## WE-RJ45-LAN-10/100BT-SMD-7498011211 (COMPANY-URL: http://www.we-online.de; CREATED-BY: Christin Zierenner; CREATED-DATE: AUG 2012; DATASHEET-URL: http://katalog.we-online.de/kataloge/eisos/media/pdf/7498011211.pdf; MANUFACTURER: Würth Elektronik eiSos GmbH)  [7498011211]
1  LED-GREEN:A
2  LED-GREEN:K
3  RJ45LAN:TD+
4  RJ45LAN:TCT
5  RJ45LAN:TD-
6  RJ45LAN:RD+
7  RJ45LAN:RCT
8  RJ45LAN:RD-
9  LED-YELLOW:A
10  LED-YELLOW:K
Z1  GND_SHIELD:P$1  pwr
Z2  GND_SHIELD:P$1  pwr

## Footprint 7498011211 (pad centres in mm)
MAX HEIGHT=13.50mm PORTS----1X1 LED --Yes
smd 0.76 x 2.03: 1 5.715,-11.68; 2 4.445,-11.68; 3 3.175,-11.68; 4 1.905,-11.68; 5 0.635,-11.68; 6 -0.635,-11.68; 7 -1.905,-11.68; 8 -3.175,-11.68; 9 -4.445,-11.68; 10 -5.715,-11.68
smd 3.3 x 3.3: Z1 9.145,0; Z2 -9.145,0
hole 3.22 at -5.715,0
hole 3.22 at 5.715,0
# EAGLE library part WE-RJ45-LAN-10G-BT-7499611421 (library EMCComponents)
Order Code 7499611421 Design THT xBase-T 10G Base-T Ports 1x1 Application Standard Tab Position UP LED (Left-Right) GREEN/YELLOW-GREEN EMI Fingers Yes

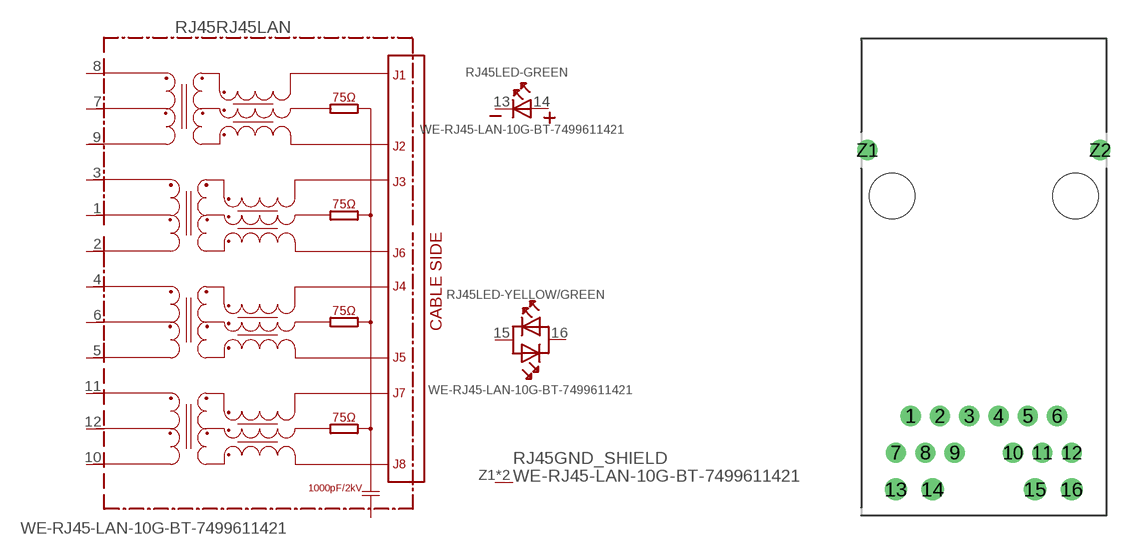
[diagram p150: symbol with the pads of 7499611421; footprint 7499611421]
Designator prefix RJ45; gates RJ45LAN=7499611421 LED-GREEN=LED2PIN LED-YELLOW/GREEN=LED-DUAL-1 GND_SHIELD=GNDPIN

## WE-RJ45-LAN-10G-BT-7499611421 (COMPANY-URL: http://www.we-online.de; CREATED-BY: Christin Zierenner; CREATED-DATE: AUG 2012; DATASHEET-URL: http://katalog.we-online.de/kataloge/eisos/media/pdf/7499611421.pdf; MANUFACTURER: Würth Elektronik eiSos GmbH)  [7499611421]
1  RJ45LAN:1
2  RJ45LAN:2
3  RJ45LAN:3
4  RJ45LAN:4
5  RJ45LAN:5
6  RJ45LAN:6
7  RJ45LAN:7
8  RJ45LAN:8
9  RJ45LAN:9
10  RJ45LAN:10
11  RJ45LAN:11
12  RJ45LAN:12
13  LED-GREEN:K
14  LED-GREEN:A
15  LED-YELLOW/GREEN:AK1
16  LED-YELLOW/GREEN:AK2
Z1  GND_SHIELD:P$1  pwr
Z2  GND_SHIELD:P$1  pwr

## Footprint 7499611421 (pad centres in mm)
MAX HEIGHT=13.87mm PORTS----1X1 LED -YES
drill 0.9: 1 -5.075,-15.24; 2 -3.045,-15.24; 3 -1.015,-15.24; 4 1.015,-15.24; 5 3.045,-15.24; 6 5.075,-15.24; 7 -6.095,-17.78; 8 -4.055,-17.78; 9 -2.025,-17.78; 10 2.025,-17.78; 11 4.055,-17.78; 12 6.095,-17.78; Z1 -8.065,3.18; Z2 8.065,3.18
drill 1.02: 13 -6.09,-20.32; 14 -3.55,-20.32; 15 3.55,-20.32; 16 6.09,-20.32
hole 3.15 at -6.35,0
hole 3.15 at 6.35,0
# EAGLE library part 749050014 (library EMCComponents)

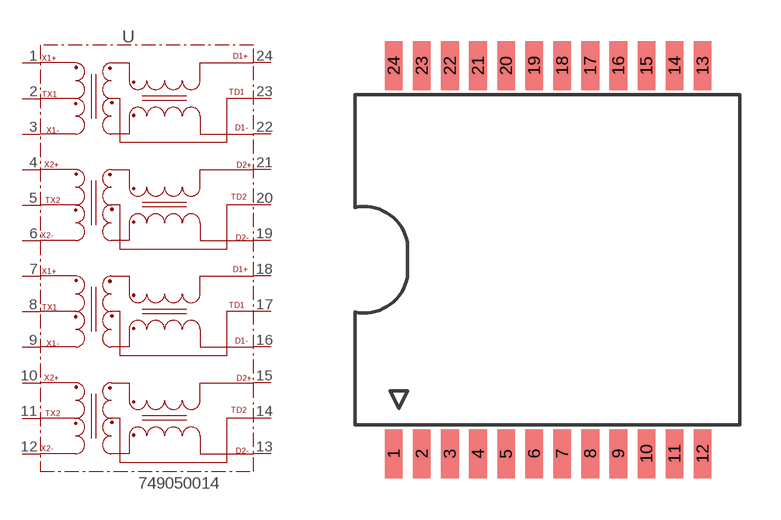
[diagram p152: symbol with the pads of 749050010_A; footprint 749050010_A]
Designator prefix -

## 749050014  [749050010_A]
1  X1+
2  TX1
3  X1-
4  X2+
5  TX2
6  X2-
7  X3+
8  TX3
9  X3-
10  X4+
11  TX4
12  X4-
13  D4-
14  TD4
15  D4+
16  D3-
17  TD3
18  D3+
19  D2-
20  TD2
21  D2+
22  D1-
23  TD1
24  D1+

## Footprint 749050010_A (pad centres in mm)
smd 0.64 x 1.778: 1 -5.61,-6.86; 2 -4.59,-6.86; 3 -3.57,-6.86; 4 -2.55,-6.86; 5 -1.53,-6.86; 6 -0.51,-6.86; 7 0.51,-6.86; 8 1.53,-6.86; 9 2.55,-6.86; 10 3.57,-6.86; 11 4.59,-6.86; 12 5.61,-6.86; 13 5.61,7.24; 14 4.59,7.24; 15 3.57,7.24; 16 2.55,7.24; 17 1.53,7.24; 18 0.51,7.24; 19 -0.51,7.24; 20 -1.53,7.24; 21 -2.55,7.24; 22 -3.57,7.24; 23 -4.59,7.24; 24 -5.61,7.24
